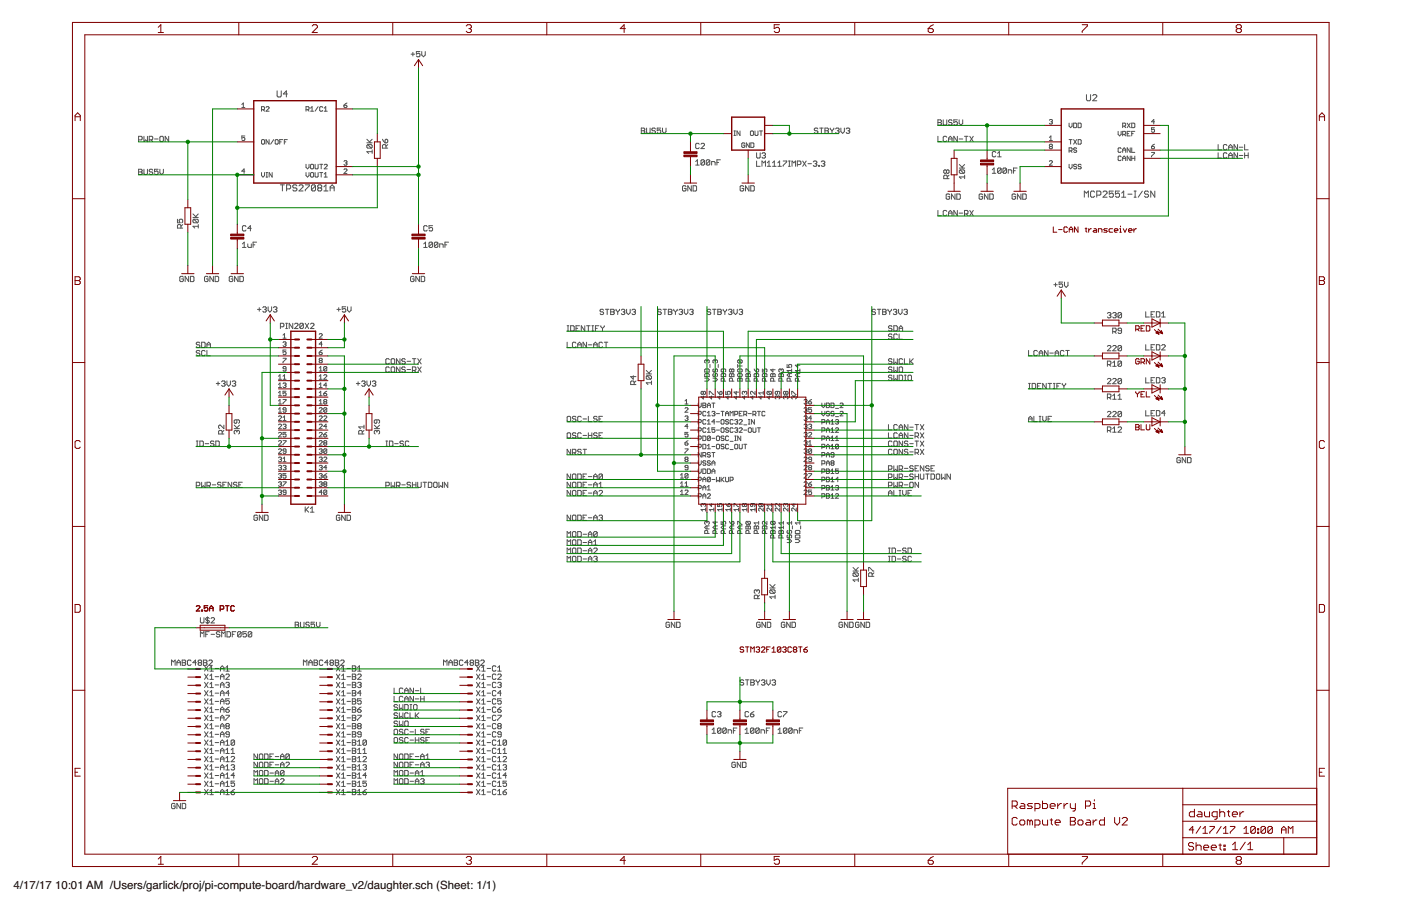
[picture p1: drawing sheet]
<svg xmlns="http://www.w3.org/2000/svg" width="432mm" height="279mm" viewBox="0 0 432 279" stroke-linecap="round" stroke-linejoin="round" font-family="sans-serif">
<defs><g id="words">
<g font-size="3.5">
<text x="4.2" y="274.2">4/17/17</text>
<text x="17" y="274.2">10:01 AM /Users/garlick/proj/pi-compute-board/hardware_v2/daughter.sch (Sheet: 1/1)</text>
</g>
</g></defs>
<g fill="none" stroke="#505050" stroke-width=".31">
<path d="M126.7 16.7h1.1M127.3 16.2v1.1M129.4 15.9h-1.1v.8l.6-.3 .5 .3v.6l-.2 .2h-.6l-.3-.2M130 15.9v1.1l.5 .5 .6-.5v-1.1M74.5 32.2l.5-.4v1.4M74.5 33.2h1M80.6 33.8h.7l.2-.7-.2-.2h-.7v1.4M81.1 33.8l.4 .5M82 33.1l.2-.2 .7 .2-.9 1.2h.9M85.4 28v1.6l.3 .3h.7l.3-.3v-1.6M88.6 29h-1.3l1-1v1.9M94.3 33.8h.7l.2-.7-.2-.2h-.7v1.4"/>
<path d="M94.8 33.8l.4 .5M95.7 34.3h.9M95.7 33.4l.5-.5v1.4M98 32.9l-.9 1.4M99.5 33.1l-.3-.2-.7 .2v1l.3 .2 .7-.2M99.9 33.4l.5-.5v1.4M99.9 34.3h1M106 32.5h.7l.2 .4-.7 .3zM106.9 31.8l-.9 .7M197.7 39.5h.8l.2 .3-.2 .5 .2 .6-.2 .2h-.8zM199.3 39.5v1.4l.3 .2h.5l.3-.2v-1.4M202 39.8l-.3-.3h-.5l-.3 .5 .3 .3h.5l.3 .6-.3 .2h-.5l-.3-.2"/>
<path d="M203.6 39.5h-1v.8l.5-.3 .5 .3v.6l-.2 .2h-.6l-.2-.2M204.2 39.5v1.1l.5 .5 .6-.5v-1.1M252.1 39.8l-.3-.3h-.6l-.2 .5 .2 .3h.6l.3 .6-.3 .2h-.6l-.2-.2M252.6 39.5h1.1M253.2 39.5v1.6M254.3 39.5h.8l.2 .3-.2 .5 .2 .6-.2 .2h-.8zM255.9 39.5l.5 .8M257 39.5l-.6 .8M257.5 39.8l.3-.3h.5l.3 .3-.3 .5M259.2 39.5v1.1l.5 .5 .5-.5v-1.1M260.8 39.8l.3-.3h.5l.3 .3-.3 .5M289.1 37h.8l.3 .2-.3 .6 .3 .5-.3 .3h-.8z"/>
<path d="M289.1 37.8h.8M290.7 37v1.3l.3 .3h.5l.3-.3v-1.3M293.4 37.2l-.2-.2h-.6l-.2 .5 .2 .3h.6l.2 .5-.2 .3h-.6l-.2-.3M295.1 37h-1.1v.8l.5-.3 .6 .3v.5l-.3 .3h-.5l-.3-.3M295.6 37v1.1l.6 .5 .5-.5v-1.1M323.4 37.1l.7-.2 .3 .2-.3 .4M323.9 37.5h.2M324.1 37.5l.3 .3-.3 .4-.7-.2M329.5 38v.9l.5 .5 .4-.5v-.9M330.9 38h.7l.2 .2v.9l-.2 .3h-.7zM332.3 38h.7l.2 .2v.9l-.2 .3h-.7zM334.9 29.2v1.6l.3 .3h.6l.3-.3v-1.6"/>
<path d="M336.8 29.5l.3-.3h.6l.3 .3v.3l-1.2 1.3h1.2M346 38.9h.7l.2-.2-.2-.7h-.7v1.4M346.5 38.9l.4 .5M347.4 38l.9 1.4M348.3 38l-.9 1.4M348.8 38h.7l.3 .2v.9l-.3 .3h-.7zM355.8 37.5h-.9l.7-.6v1.3M355.8 39.4h-.9v.7l.5-.2 .4 .2-.2 .7-.7-.2M42.7 43.1h.8l.3-.2v-.6l-.3-.3h-.8v1.7M42.7 52.2h.8l.3 .3-.3 .5 .3 .6-.3 .2h-.8zM42.7 53h.8M44.4 52.2v1.4l.2 .2h.6l.2-.2v-1.4"/>
<path d="M44.4 42v1.7l.5-.6 .5 .6v-1.7M46 43.1h.8l.3-.2v-.6l-.3-.3h-.8v1.7M46.5 43.1l.6 .6M47.1 52.5l-.3-.3h-.5l-.3 .3 .3 .5h.5l.3 .3-.3 .5h-.5l-.3-.2M47.6 42.9h1.1M48.7 52.2h-1.1v.8l.6-.3 .5 .3v.6l-.2 .2h-.6l-.3-.2M49.3 52.2v1.1l.5 .5 .6-.5v-1.1M49.3 42.3l.3-.3h.5l.3 .3v1.1l-.3 .3h-.5l-.3-.3zM52 42v1.7l-1.1-1.7v1.7M75.5 41.9h-1v.7l.5-.2 .5 .2-.3 .7-.7-.2M75.5 52.8h-1l.7-.7v1.4M80.6 43.3l.2-.2 .7 .2v.9l-.2 .2-.7-.2z"/>
<path d="M80.6 53.2v.9l.5 .5 .4-.5v-.9M82 54.6h.5M82 53.2h.5M82.2 53.2v1.4M82.9 43.1v1.3l-.9-1.3v1.3M83.9 53.2v1.4l-.9-1.4v1.4M84.3 43.1l-.9 1.3M84.8 43.3l.2-.2 .7 .2v.9l-.2 .2-.7-.2zM86.2 43.8h.5M86.4 57h1.3M87 57v1.9M87.1 43.1h-.9v1.3"/>
<path d="M87.6 43.8h.5M88.3 58.3h1l.3-.3v-.7l-.3-.3h-1v1.9M88.6 43.1h-1v1.3M91.5 57.3l-.3-.3h-.6l-.4 .3 .4 .7h.6l.3 .3-.3 .6h-.6l-.4-.3M92.2 57.3l.3-.3h.6l.3 .3v.3l-1.2 1.3h1.2M94.1 57h1.2v.3l-1.2 1.3v.3M94.3 50.7v.9l.5 .5 .4-.5v-.9M94.3 53.2v.9l.5 .5 .4-.5v-.9M95.7 53.4l.2-.2 .7 .2v1l-.2 .2-.7-.2zM95.7 50.9l.2-.2 .7 .2v.9l-.2 .3-.7-.3zM97.1 50.7v1.1l.2 .3 .7-.3v-1.1M97.1 53.2v1.2l.2 .2 .7-.2v-1.2"/>
<path d="M97.2 57.3l-.3-.3h-.6l-.3 .3v1.3M97.2 57.3v1.3l-.3 .3h-.6l-.3-.3M97.2 57.3l-1.2 1.3M98.2 58l-.3-.4 .3-.6h.6l.4 .3-.4 .7M98.2 58h.6M98.2 58l-.3 .3 .3 .6h.6l.4-.3-.4-.6M98.5 53.2h1M98.5 50.7h1M99 50.7v1.4M99 53.2v1.4M99.8 58.9h1.3M99.8 57.6l.7-.6v1.9"/>
<path d="M99.9 50.9l.3-.2 .7 .2-1 1.2h1M99.9 54.6h1M99.9 53.7l.5-.5v1.4M101.7 58h1.3M101.7 58.9v-1.3l.7-.6 .6 .6v1.3M106 49.8l.7-.2 .2 .2-.2 .4M106 52.3l.2-.2 .7 .2-.9 1.2h.9M106.5 50.2h.2M106.7 50.2l.2 .3-.2 .4-.7-.2M113.1 44h1.6M113.1 42.9l1.1 1.1M113.3 44.6h1.1l.3 .3v.5l-.3 .3"/>
<path d="M113.3 44.6l-.2 .3v.5l.2 .3h1.1M113.3 44.6l1.1 1.1M114.7 46.8h-1.6l.5 .5M114.7 46.2v1.1M114.7 42.9l-.8 .9M117.9 42.9l.8 1.1M118.7 43.2l.3-.3 .5 .3v.6l-.3 .2h-.5zM119 45.7v-.8l-.3-.3h-.5l-.3 .3v.8h1.6M119.5 44.6l-.5 .5M197.7 40.3h.8M211.4 57.6l-.2-.3h-.6l-.2 .3v1l.2 .3h.6l.2-.3v-.5h-.5M213.1 57.3v1.6l-1.1-1.6v1.6"/>
<path d="M213.6 57.3h.8l.3 .3v1l-.3 .3h-.8zM214.4 49.8l.5-.5v1.6M214.4 50.9h1.1M215.5 44.5l-.3-.3h-.5l-.3 .3v1.1l.3 .2h.5l.3-.2M216 44.5l.3-.3h.6l.2 .3v.2l-1.1 1.1h1.1M217.1 49.6l-.2-.3h-.6l-.3 .3v1M217.1 49.6v1l-.2 .3h-.6l-.3-.3M217.1 49.6l-1.1 1M218.8 49.6v1l-.3 .3h-.5l-.3-.3M218.8 49.6l-.3-.3h-.5l-.3 .3v1M218.8 49.6l-1.1 1M219.3 50.9v-1.1h.8l.3 .3v.8"/>
<path d="M221 50.1h.5M222 49.3h-1v1.6M226.2 41.8h.5M226.2 40.4h.5M226.4 40.4v1.4M228.1 40.4v1.4l-1-1.4v1.4M229.2 57.6l-.3-.3h-.5l-.3 .3v1l.3 .3h.5l.3-.3v-.5h-.5M229.6 44.3l-.3-.2-.7 .2v.9l.3 .3 .7-.3v-.4h-.5M230.8 57.3v1.6l-1-1.6v1.6M230.9 44.1v1.4l-.9-1.4v1.4M231.4 57.3h.8l.3 .3v1l-.3 .3h-.8zM231.4 44.1h.7l.2 .2v.9l-.2 .3h-.7z"/>
<path d="M231.5 40.4l.7 .2v1l-.2 .2-.7-.2v-1zM232.7 40.4v1.2l.2 .2 .7-.2v-1.2M233.2 47.1v1.4l.3 .2h.5l.3-.2v-1.4M233.2 49.7v1.6h1.1M234.1 40.4h.9M234.5 40.4v1.4M234.8 51.3v-1.6l.6 .5 .5-.5v1.6M234.8 47.4l.3-.3h.5l.3 .3-.3 .5M235.4 47.9h.2M235.6 47.9l.3 .3-.3 .5h-.5l-.3-.2M236.5 51.3h1.1M236.5 50.2l.5-.5v1.6"/>
<path d="M238.1 51.3h1.1M238.1 50.2l.6-.5v1.6M239.8 51.3h1M239.8 50.2l.5-.5v1.6M241.4 49.7h1.1l-1.1 1.6M243 51.3h.6M243 49.7h.6M243.3 49.7v1.6M244.1 51.3v-1.6l.6 .5 .5-.5v1.6M245.7 50.8h.9l.2-.3v-.6l-.2-.2h-.9v1.6M247.4 49.7l1.1 1.6M248.5 49.7l-1.1 1.6"/>
<path d="M249 50.5h1.1M250.7 49.9l.2-.2h.6l.3 .2-.3 .6M251.2 50.5h.3M251.5 50.5l.3 .3-.3 .5h-.6l-.2-.3M252.3 51h.3v.3h-.3zM253.1 49.9l.3-.2h.5l.3 .2-.3 .6M253.7 50.5h.2M253.9 50.5l.3 .3-.3 .5h-.5l-.3-.3M254.3 40.3h.8M256.4 40.3v.8M258.1 40.3h.2M258.3 40.3l.3 .3-.3 .5h-.5l-.3-.2"/>
<path d="M261.3 40.3h.3M261.6 40.3l.3 .3-.3 .5h-.5l-.3-.2M289.1 42v1.7h1.1M291.7 52.6l-.3-.2-.5 .2v.6l.2 .3 .6-.3M291.7 52.6l.3-.2 .5 .2v.6l-.3 .3-.5-.3M291.7 52.6v.6M291.8 42.3l-.3-.3h-.5l-.3 .3v1.1l.3 .3h.5l.3-.3M292 55.1v-.8l-.3-.3h-.6l-.2 .3v.8h1.6M292.4 43.7v-1.1l.5-.6 .5 .6v1.1M292.4 42.9h1M292.5 54l-.5 .6M294.3 59.8v1.6l-1.1-1.6v1.6"/>
<path d="M294.9 59.8h.8l.3 .3v1.1l-.3 .2h-.8zM295.1 42v1.7l-1.1-1.7v1.7M295.6 42.9h1.1M295.7 51.8h1.6M295.7 50.7l1.1 1.1M296 52.4h1l.3 .2v.6l-.3 .3M296 52.4l-.3 .2v.6l.3 .3h1M296 52.4l1 1.1M297.3 42h1M297.3 54.6h-1.6l.5 .5M297.3 54v1.1M297.3 50.7l-.8 .9"/>
<path d="M297.8 42v1.7M298.9 42l1.1 1.7M300 42l-1.1 1.7M304.5 59.8v1.6l-1.1-1.6v1.6M305.1 59.8h.8l.2 .3v1.1l-.2 .2h-.8zM305.8 53.4h1.1M305.8 52.4l.6-.6v1.6M306.9 47l-.3-.3h-.5l-.3 .3v1.1l.3 .3h.5l.3-.3M307.5 47.3l.5-.6v1.7M307.5 48.4h1.1M308.6 52.1v1.1l-.3 .2h-.6l-.2-.2M308.6 52.1l-.3-.3h-.6l-.2 .3v1.1"/>
<path d="M308.6 52.1l-1.1 1.1M310.2 52.1v1.1l-.3 .2h-.5l-.3-.2M310.2 52.1l-.3-.3h-.5l-.3 .3v1.1M310.2 52.1l-1.1 1.1M310.7 53.4v-1h.9l.2 .2v.8M312.4 52.6h.5M313.5 51.8h-1.1v1.6M314.7 59.8v1.6l-1.1-1.6v1.6M315.2 59.8h.8l.3 .3v1.1l-.3 .2h-.8zM323.4 49.8l.3-.2 .7 .2-1 1.1h1M323.4 43.3h1M323.4 42.4l.5-.5v1.4"/>
<path d="M323.7 45.2l-.3 .2 .3 .5 .7-.3-.3-.4M323.7 45.2l-.3-.3 .3-.4 .7 .2-.3 .5M323.7 45.2h.4M329.5 46.5h.7l.2-.2-.2-.7h-.7v1.4M329.5 43.1h.9M329.5 50.7v.9l.5 .5 .4-.5v-.9M330 43.1v1.3M330 46.5l.4 .5M330.9 43.1l.9 1.3M331.8 45.8l-.2-.2-.7 .2 .2 .5 .7 .2-.2 .5-.7-.2M331.8 50.9l-.2-.2-.7 .2 .2 .5 .7 .2-.2 .5-.7-.3M331.8 43.1l-.9 1.3"/>
<path d="M332.3 43.1h.7l.2 .2v.9l-.2 .2h-.7zM333.2 50.9l-.2-.2-.7 .2 .2 .5 .7 .2-.2 .5-.7-.3M337.4 59.2l-.3-.3h-.7l-.3 .3v1.3l.3 .3h.7l.3-.3M340 59.2l.3-.3h.6l.3 .3v.4l-1.2 1.2h1.2M343.1 58.9h-1.2v1l.9-.3 .3 .3v.6l-.3 .3h-.6l-.3-.3M344.6 40.5v.9l.5 .5 .4-.5v-.9M345 58.9h-1.2v1l.9-.3 .3 .3v.6l-.3 .3h-.6l-.3-.3M345.5 45.8l-.2-.2-.7 .2v1l.2 .2 .7-.2M345.5 48.4l-.2-.3-.7 .3v.9l.2 .2 .7-.2M345.7 59.6l.6-.7v1.9M346 47v-.9l.5-.5 .4 .5v.9M346 46.3h.9"/>
<path d="M346 41.4h.7l.2-.2-.2-.7h-.7v1.4M346 49.5v-.9l.5-.5 .4 .5v.9M346 48.8h.9M346.5 41.4l.4 .5M347.4 41.2h.5M347.6 59.9h1.3M348.3 40.5h-.9v1.4h.9M348.3 45.6v1.4l-.9-1.4v1.4M348.3 48.1v1.4l-.9-1.4v1.4M348.8 45.6v1.4h1M348.8 48.1v1.4M348.8 41.2h.5"/>
<path d="M348.8 48.8h1M349.5 58.9h.7M349.8 40.5h-1v1.4M349.8 48.1v1.4M349.9 58.9v1.9M352.1 58.9l-1.3 1.9M354 59.2l-.3-.3h-.6l-.4 .7 .4 .3h.6l.3 .6-.3 .3h-.6l-.4-.3M354.9 47h.9l-.9 1.4M354.9 45.2h.7l.2 .4-.7 .3zM355.8 44.5l-.9 .7M355.9 58.9v1.9l-1.2-1.9v1.9M375.4 47.1v1.6h1.1"/>
<path d="M375.4 44.6v1.6h1.1M378.1 44.9l-.2-.3h-.6l-.2 .3v1l.2 .3h.6l.2-.3M378.1 47.4l-.2-.3h-.6l-.2 .3v1.1l.2 .2h.6l.2-.2M378.7 47.9h1.1M378.7 46.2v-1.1l.5-.5 .6 .5v1.1M378.7 48.7v-1l.5-.6 .6 .6v1M378.7 45.4h1.1M381.4 44.6v1.6l-1.1-1.6v1.6M381.4 47.1v1.6l-1.1-1.6v1.6M382 47.9h1.1M382 45.4h1.1M383.6 47.9h1.1"/>
<path d="M383.6 44.6v1.6h1.1M383.6 47.1v1.6M384.7 47.1v1.6M54.7 67.6v1.1h.8l-.3-.5 .3-.6h.5l.3 .3v.5l-.3 .3M55.8 70.3v-.8l-.3-.2h-.6l-.2 .2v.8h1.6M56.3 69.3l-.5 .5M59.5 67.1h1.6M59.5 66l1.1 1.1M59.8 67.6h1l.3 .3v.5l-.3 .3M59.8 67.6l-.3 .3v.5l.3 .3h1M59.8 67.6l1 1.1M61.1 69.3v1"/>
<path d="M61.1 69.8h-1.6l.5 .5M61.1 66l-.8 .8M74.7 75.2l.6-.5v1.6M74.7 76.3h1.1M75.8 69.9l-.3-.3h-.5l-.3 .3v1.1l.3 .2h.5l.3-.2M76.4 75.2v.8l.2 .3h.8v-1.1M77.4 70.4h-1l.8-.8v1.6M78 75.5h.5M79.1 74.7h-1.1v1.6M130.6 76.3h1.1M130.6 75.2l.5-.5v1.6M131.7 69.9l-.3-.3h-.5l-.3 .3v1.1l.3 .2h.5l.3-.2"/>
<path d="M133.3 75v1l-.2 .3h-.6l-.3-.3M133.3 75l-.2-.3h-.6l-.3 .3v1M133.3 69.6h-1.1v.8l.6-.3 .5 .3v.6l-.2 .2h-.6l-.3-.2M133.3 75l-1.1 1M135 75v1l-.3 .3h-.6l-.2-.3M135 75l-.3-.3h-.6l-.2 .3v1M135 75l-1.1 1M135.5 76.3v-1.1h.8l.3 .3v.8M137.1 75.5h.6M138.2 74.7h-1.1v1.6M289.1 64.9v1.6h1.1M291.8 65.2l-.3-.3h-.5l-.3 .3v1.1l.3 .2h.5l.3-.2"/>
<path d="M292.4 66.5v-1.1l.5-.5 .5 .5v1.1M292.4 65.7h1M292.7 60.1l-.3-.3h-.5l-.3 .3v1.1l.3 .2h.5l.3-.2v-.6h-.5M295.1 64.9v1.6l-1.1-1.6v1.6M295.6 65.7h1.1M297.3 66h.8l.2-.3v-.5l-.2-.3h-.8v1.6M297.8 66l.5 .5M298.9 64.9l1.1 1.6M300 64.9l-1.1 1.6M302.9 60.1l-.3-.3h-.6l-.2 .3v1.1l.2 .2h.6l.3-.2v-.6h-.6M313 60.1l-.3-.3h-.5l-.3 .3v1.1l.3 .2h.5l.3-.2v-.6h-.5M334.2 60.8v-1.9l.6 .7 .6-.7v1.9"/>
<path d="M338 60.2h1l.3-.3v-.7l-.3-.3h-1v1.9M345.7 60.8h1.3M349.5 60.8h.7M56.5 85.5l-.3-.3h-.5l-.3 .3v1.1l.3 .2h.5l.3-.2v-.6h-.5M58.1 85.2v1.6l-1-1.6v1.6M58.7 85.2h.8l.3 .3v1.1l-.3 .2h-.8zM64.1 85.5l-.2-.3h-.6l-.3 .3v1.1l.3 .2h.6l.2-.2v-.6h-.5M65.8 85.2v1.6l-1.1-1.6v1.6M66.3 85.2h.8l.3 .3v1.1l-.3 .2h-.8zM71.8 85.5l-.3-.3h-.6l-.2 .3v1.1l.2 .2h.6l.3-.2v-.6h-.6M73.4 85.2v1.6l-1.1-1.6v1.6M73.9 85.2h.8l.3 .3v1.1l-.3 .2h-.8z"/>
<path d="M79.4 95.4h1M79.9 94.9v1.1M81 94.9l.3-.3h.5l.3 .3-.3 .5M81.5 95.4h.3M81.8 95.4l.3 .3-.3 .5h-.5l-.3-.2M82.6 94.6v1.1l.6 .5 .5-.5v-1.1M84.3 94.9l.2-.3h.6l.2 .3-.2 .5M84.8 95.4h.3M85.1 95.4l.2 .3-.2 .5h-.6l-.2-.2M88.1 99.7h.5M88.3 99.7v1.6M90.2 99.7v1.6l-1.1-1.6v1.6"/>
<path d="M90.8 100l.3-.3h.5l.3 .3v.2l-1.1 1.1h1.1M93.5 100l-.3-.3h-.5l-.3 .3v1M93.5 100v1l-.3 .3h-.5l-.3-.3M93.5 100l-1.1 1M94.1 99.7l1 1.6M95.1 99.7l-1 1.6M95.7 100l.3-.3h.5l.3 .3v.2l-1.1 1.1h1.1M103.8 95.4h1.1M104.4 94.9v1.1M106.6 94.6h-1.1v.8l.5-.2 .6 .2v.6l-.3 .2h-.6l-.2-.2M107.1 94.6v1.1l.6 .5 .5-.5v-1.1M127.6 85.5l-.3-.3h-.5l-.3 .3v1.1l.3 .2h.5l.3-.2v-.6h-.5"/>
<path d="M129.3 85.2v1.6l-1.1-1.6v1.6M129.8 85.2h.8l.3 .3v1.1l-.3 .2h-.8zM186 95.7l-.2-.3h-.6l-.2 .5 .2 .3h.6l.2 .5-.2 .3h-.6l-.2-.3M186.6 95.4h1.1M187.1 95.4v1.6M188.2 95.4h.8l.3 .3-.3 .5 .3 .5-.3 .3h-.8zM188.2 96.2h.8M189.9 95.4l.5 .8M190.4 96.2v.8M190.9 95.4v.3l-.5 .5M191.5 95.7l.3-.3h.5l.3 .3-.3 .5M192 96.2h.3"/>
<path d="M192.3 96.2l.3 .3-.3 .5h-.5l-.3-.3M193.1 95.4v1.1l.6 .5 .5-.5v-1.1M194.8 95.7l.3-.3h.5l.3 .3-.3 .5M195.3 96.2h.3M195.6 96.2l.3 .3-.3 .5h-.5l-.3-.3M203.8 95.7l-.3-.3h-.5l-.3 .5 .3 .3h.5l.3 .5-.3 .3h-.5l-.3-.3M204.4 95.4h1M204.9 95.4v1.6M206 95.4h.8l.3 .3-.3 .5 .3 .5-.3 .3h-.8zM206 96.2h.8M207.6 95.4l.6 .8M208.2 96.2v.8"/>
<path d="M208.7 95.4v.3l-.5 .5M209.3 95.7l.2-.3h.6l.3 .3-.3 .5M209.8 96.2h.3M210.1 96.2l.3 .3-.3 .5h-.6l-.2-.3M210.9 95.4v1.1l.6 .5 .5-.5v-1.1M212.6 95.7l.2-.3h.6l.2 .3-.2 .5M213.1 96.2h.3M213.4 96.2l.2 .3-.2 .5h-.6l-.2-.3M219.1 95.7l-.3-.3h-.6l-.2 .5 .2 .3h.6l.3 .5-.3 .3h-.6l-.2-.3M219.6 95.4h1.1M220.1 95.4v1.6M221.2 95.4h.9l.2 .3-.2 .5 .2 .5-.2 .3h-.9z"/>
<path d="M221.2 96.2h.9M222.9 95.4l.5 .8M223.4 96.2v.8M224 95.4v.3l-.6 .5M224.5 95.7l.3-.3h.5l.3 .3-.3 .5M225 96.2h.3M225.3 96.2l.3 .3-.3 .5h-.5l-.3-.3M226.1 95.4v1.1l.6 .5 .5-.5v-1.1M227.8 95.7l.2-.3h.6l.3 .3-.3 .5M228.3 96.2h.3M228.6 96.2l.3 .3-.3 .5h-.6l-.2-.3M269.8 95.7l-.2-.3h-.6l-.2 .3 .2 .5h.6l.2 .3-.2 .5h-.6l-.2-.3"/>
<path d="M270.4 95.4h1.1M270.9 95.4v1.6M272 95.4h.8l.3 .3-.3 .5 .3 .5-.3 .3h-.8zM272 96.2h.8M273.7 95.4v.3l.5 .5M274.2 96.2v.8M274.7 95.4l-.5 .8M275.3 95.7l.3-.3h.5l.3 .3-.3 .5M275.8 96.2h.3M276.1 96.2l.3 .3-.3 .5h-.5l-.3-.3M276.9 95.4v1.1l.6 .5 .5-.5v-1.1M278.6 95.7l.2-.3h.6l.3 .3-.3 .5"/>
<path d="M279.1 96.2h.3M279.4 96.2l.3 .3-.3 .5h-.6l-.2-.3M324.8 87.8h1.1M325.3 87.3v1M327.5 87h-1.1v.8l.6-.3 .5 .3v.5l-.2 .3h-.6l-.3-.3M328.1 87v1.1l.5 .5 .6-.5v-1.1M341.3 96.7l.3-.3h.5l.3 .3-.3 .5M341.8 97.2h.3M342.1 97.2l.3 .3-.3 .5h-.5l-.3-.3M342.9 96.7l.3-.3h.6l.2 .3-.2 .5M343.5 97.2h.3M343.8 97.2l.2 .3-.2 .5h-.6l-.3-.3"/>
<path d="M345.7 96.7l-.3-.3h-.6l-.2 .3v1M345.7 96.7v1l-.3 .3h-.6l-.2-.3M345.7 96.7l-1.1 1M353.1 96.1v1.7h1.1M354.8 96.9h.5M355.9 96.1h-1.1v1.7h1.1M356.4 96.1h.8l.3 .3v1.1l-.3 .3h-.8zM358 96.7l.6-.6v1.7M358 97.8h1.1M61.6 105.8l-.3-.3h-.5l-.3 .3 .3 .5h.5l.3 .3-.3 .6h-.5l-.3-.3M61.6 108.4l-.3-.3h-.5l-.3 .3 .3 .5h.5l.3 .3-.3 .5h-.5l-.3-.3M62.1 105.5h.8l.3 .3v1.1l-.3 .3h-.8z"/>
<path d="M63.2 108.4l-.3-.3h-.5l-.3 .3v1l.3 .3h.5l.3-.3M63.8 107.2v-1.1l.5-.6 .6 .6v1.1M63.8 108.1v1.6h1.1M63.8 106.3h1.1M66.7 118.3h1M67.2 117.8v1M68.3 117.8l.3-.3h.5l.3 .3-.3 .5M68.8 118.3h.3M69.1 118.3l.3 .3-.3 .5h-.5l-.3-.3M69.9 117.5v1.1l.6 .5 .5-.5v-1.1M71.6 117.8l.2-.3h.6l.2 .3-.2 .5M72.1 118.3h.3"/>
<path d="M72.4 118.3l.2 .3-.2 .5h-.6l-.2-.3M85.8 117h1M85.8 116l.5-.4v1.4M85.8 118.6l.5-.5v1.4M85.8 119.5h1M86.4 100.8h.8l.3-.3v-.5l-.3-.3h-.8v1.6M87.2 103.4l.5-.5v1.4M87.2 117h1M87.2 116l.5-.4v1.4M87.2 104.3h1M87.2 105.6l.7-.2 .3 .2-.3 .5M87.2 110.5h1l-1 1.4"/>
<path d="M87.2 118.3l.7-.2 .3 .2-.3 .5M87.7 106.1h.2M87.7 118.8h.2M87.9 106.1l.3 .3-.3 .4-.7-.2M87.9 118.8l.3 .2-.3 .5-.7-.2M88.1 101.3h.5M88.2 107.9h-1v.7l.5-.2 .5 .2-.3 .8-.7-.3M88.2 113.7h-.7l-.3-.2 .3-.5 .7 .3v.9l-.3 .2-.7-.2M98.4 108.6h.7l.2 .5-.7 .3zM98.4 117h.9M98.4 103.1l.2-.2 .7 .2-.9 1.2h.9M98.4 114.4h.9"/>
<path d="M98.4 113.5l.4-.5v1.4M98.4 116l.4-.4v1.4M98.4 118.6l.4-.5v1.4M98.4 119.5h.9M98.6 111.2l-.2-.2 .2-.5 .7 .2-.2 .5M98.6 111.2l-.2 .2 .2 .5 .7-.2-.2-.5M98.6 111.2h.5M99.3 106.1h-.9l.7-.7v1.4M99.3 107.9l-.9 .7M99.8 115.8l.2-.2 .7 .2-.9 1.2h.9M100.7 118.8h-.9l.7-.7v1.4M100.7 113.3v.9l-.2 .2-.7-.2"/>
<path d="M100.7 113.3l-.7-.3-.2 .3v.9M100.7 113.3l-.9 .9M109.8 118.3h1.1M110.4 117.8v1M111.5 117.8l.2-.3h.6l.2 .3-.2 .5M112 118.3h.3M112.3 118.3l.2 .3-.2 .5h-.6l-.2-.3M113.1 117.5v1.1l.5 .5 .6-.5v-1.1M114.7 117.8l.3-.3h.5l.3 .3-.3 .5M115.3 118.3h.2M115.5 118.3l.3 .3-.3 .5h-.5l-.3-.3M120 110.9l-.3-.3h-.5l-.3 .3v1.1l.3 .2h.5l.3-.2"/>
<path d="M120 113.4l-.3-.2h-.5l-.3 .2v1.1l.3 .3h.5l.3-.3M120.5 110.9l.3-.3h.6l.2 .3v1.1l-.2 .2h-.6l-.3-.2zM120.5 113.4l.3-.2h.6l.2 .2v1.1l-.2 .3h-.6l-.3-.3zM123.3 110.6v1.6l-1.1-1.6v1.6M123.3 113.2v1.6l-1.1-1.6v1.6M124.9 113.4l-.3-.2h-.5l-.3 .5 .3 .3h.5l.3 .5-.3 .3h-.5l-.3-.3M124.9 110.9l-.3-.3h-.5l-.3 .5 .3 .3h.5l.3 .6-.3 .2h-.5l-.3-.2M125.5 114h1.1M125.5 111.4h1.1M127.1 114.2h.8l.3-.2v-.6l-.3-.2h-.8v1.6M127.1 110.6h1.1M127.6 110.6v1.6"/>
<path d="M127.6 114.2l.6 .6M128.7 113.2l1.1 1.6M128.7 110.6l1.1 1.6M129.8 113.2l-1.1 1.6M129.8 110.6l-1.1 1.6M174.8 105.5v1.7h1.1M174.8 100.5h.5M174.8 102.1h.5M175.1 100.5v1.6M175.9 100.5h.8l.3 .2v1.1l-.3 .3h-.8zM177.5 105.8l-.3-.3h-.5l-.3 .3v1.1l.3 .3h.5l.3-.3M177.5 101.3h.6"/>
<path d="M178.1 106.3h1.1M178.1 107.2v-1.1l.5-.6 .6 .6v1.1M178.6 100.5h-1.1v1.6h1.1M180.2 100.5v1.6l-1-1.6v1.6M180.8 105.5v1.7l-1.1-1.7v1.7M180.8 100.5h1.1M181.3 106.3h1.1M181.3 100.5v1.6M182.4 100.5h.6M182.4 102.1h.6M182.7 100.5v1.6M183 106.3h1.1"/>
<path d="M183 107.2v-1.1l.5-.6 .6 .6v1.1M183.5 101.3h.6M184.6 100.5h-1.1v1.6M185.2 100.5l.5 .8M185.7 105.8l-.3-.3h-.5l-.3 .3v1.1l.3 .3h.5l.3-.3M185.7 101.3v.8M186.2 105.5h1.1M186.2 100.5v.2l-.5 .6M186.8 105.5v1.7M195.2 115.9v1l-.8-.8h1.6M195.5 118.6v-.8l-.3-.3h-.6l-.2 .3v.8h1.6M196 117.5l-.5 .5"/>
<path d="M199.2 115.3h1.6M199.2 114.2l1.1 1.1M199.4 115.9h1.1l.3 .2v.6l-.3 .2M199.4 115.9l-.2 .2v.6l.2 .2h1.1M199.4 115.9l1.1 1M200.8 118h-1.6l.5 .6M200.8 117.5v1.1M200.8 114.2l-.8 .8M217.2 116.6h.9l.5 .5-.5 .4h-.9M217.4 113.8h1l.2 .2v.7h-1.4v-.7zM217.4 115.2h1l.2 .2v.7h-1.4v-.7zM217.9 111.2l-.2-.2-.5 .2 .2 .7"/>
<path d="M217.9 111.2v.3M217.9 111.2l.2-.2 .5 .2-.2 .7M218.8 112.4v.9M219.7 116.6h1l.4 .5-.4 .4h-1M220 113.8l-.3 .2 .3 .7 .4-.2 .3-.7 .4 .2-.2 .7M220 115.2l-.3 .2 .3 .7 .4-.2 .3-.7 .4 .2-.2 .7M220.4 111.2l.3-.2 .4 .2-.2 .7M220.4 111.2v.3M220.4 111.2l-.2-.2-.5 .2 .3 .7M221.4 112.4v.9M222.3 115.4l.2-.2 .5 .2 .4-.2 .3 .2v.7h-1.4zM223 113.8v.7l-.3 .2-.4-.2 .2-.7h.9l.3 .2-.3 .7"/>
<path d="M223 115.4v.7M223.2 117.5v-.7l-.7-.2-.2 .2v.7h1.4M224.8 115.4l.2-.2 .5 .2 .5-.2 .2 .2v.7h-1.4zM225.5 114l-.2-.2-.5 .2 .2 .7 .5-.2M225.5 114v.5M225.5 115.4v.7M225.5 114l.2-.2 .5 .2-.2 .7-.5-.2M225.7 117.5v-.7l-.7-.2-.2 .2v.7h1.4M227.4 115.4l.2-.2h.9l.2 .7-.2 .2h-.9zM227.4 116.8l.2-.2 .4 .2 .5-.2 .2 .2v.7h-1.3zM227.4 114l.2-.2h.9l.2 .7-.2 .2h-.9zM227.4 112.4v.9"/>
<path d="M227.4 112.9h1.3M227.6 111l-.2 .2 .2 .7h.9M227.6 111h.9l.2 .2-.2 .7M227.6 111l.9 .9M228 116.8v.7M229.9 114.7v-.9l1.4 .9M229.9 115.4l.2-.2 .5 .2 .5-.2 .2 .2v.7h-1.4zM230.6 115.4v.7M230.8 117.5v-.7l-.7-.2-.2 .2v.7h1.4M232.4 115.4l.3-.2 .4 .2 .5-.2 .2 .2v.7h-1.4zM232.4 113.8l.7 .9M233.1 114l.5-.2 .2 .7-.7 .2z"/>
<path d="M233.1 115.4v.7M233.4 117.5v-.7l-.7-.2-.3 .2v.7h1.4M235 113.8v.9h.7l-.3-.4 .3-.5 .7 .2-.3 .7M235 115.4l.2-.2 .5 .2 .4-.2 .3 .2v.7h-1.4zM235.7 115.4v.7M235.9 117.5v-.7l-.7-.2-.2 .2v.7h1.4M237.5 115.4l.2-.2 .5 .2 .5-.2 .2 .2v.7h-1.4zM238.2 113.8v.9l-.7-.7h1.4M238.2 115.4v.7M238.4 117.5v-.7l-.7-.2-.2 .2v.7h1.4M240.1 115.4l.2-.2 .4 .2 .5-.2 .2 .2v.7h-1.3zM240.7 114v.3"/>
<path d="M240.7 115.4v.7M240.7 114l.3-.2 .4 .2-.2 .7M240.7 114l-.2-.2-.4 .2 .2 .7M241 117.5v-.7l-.7-.2-.2 .2v.7h1.3M242.6 112.4v.9h.7l-.2-.4 .2-.5 .7 .2-.2 .7M243.3 115.2v.9M243.5 117.5v-.7l-.7-.2-.2 .2v.7h1.4M244 115.2h-.9l-.5 .5 .5 .4h.9M244 113.8v.9M244 114.3h-1.4l.5 .4M245.8 112.4v.9l-.7-.7h1.4M245.8 115.2v.9"/>
<path d="M246.1 117.5v-.7l-.7-.2-.3 .2v.7h1.4M246.5 115.2h-.9l-.5 .5 .5 .4h.9M246.5 113.8v.9M246.5 114.3h-1.4l.5 .4M274.9 103.3l-.2-.3h-.6l-.3 .3 .3 .5h.6l.2 .3-.2 .5h-.6l-.3-.2M274.9 110.9l-.2-.3h-.6l-.3 .3 .3 .5h.6l.2 .3-.2 .5h-.6l-.3-.2M274.9 100.7l-.2-.2h-.6l-.3 .2 .3 .6h.6l.2 .2-.2 .6h-.6l-.3-.3M274.9 113.4l-.2-.2h-.6l-.3 .2 .3 .6h.6l.2 .2-.2 .6h-.6l-.3-.3M274.9 116l-.2-.3h-.6l-.3 .3 .3 .5h.6l.2 .3-.2 .5h-.6l-.3-.2M275.5 115.7v1.6l.5-.5 .6 .5v-1.6M275.5 100.5h.8l.3 .2v1.1l-.3 .3h-.8zM275.5 110.6v1.6l.5-.5 .6 .5v-1.6"/>
<path d="M275.5 113.2v1.6l.5-.6 .6 .6v-1.6M276.6 103.3l-.3-.3h-.6l-.2 .3v1.1l.2 .2h.6l.3-.2M277.1 115.7h.8l.3 .3v1.1l-.3 .2h-.8zM277.1 102.1v-1.1l.5-.5 .6 .5v1.1M277.1 103v1.6h1.1M277.1 101.3h1.1M277.4 113.2h.5l.3 .2v1.1l-.3 .3h-.5l-.3-.3v-1.1zM278.2 110.9l-.3-.3h-.5l-.3 .3v1.1l.3 .2h.5l.3-.2M278.7 110.6v1.6h1.1M278.7 115.7h.6M278.7 117.3h.6M279 115.7v1.6"/>
<path d="M279.8 116l.3-.3h.5l.3 .3v1.1l-.3 .2h-.5l-.3-.2zM280.4 110.6v1.6M280.6 111.4l.9 .8M281.5 110.6l-1.1 1.1M317 118.2h.6M317 108.1v1.6h1.1M317 119.9h.6M317.3 118.2v1.7M318.1 118.2h.8l.3 .3v1.1l-.3 .3h-.8zM319.7 108.4l-.2-.3h-.6l-.3 .3v1l.3 .3h.6l.2-.3M319.7 119h.6M320.3 108.9h1.1"/>
<path d="M320.3 109.7v-1.1l.5-.5 .6 .5v1.1M320.8 118.2h-1.1v1.7h1.1M322.5 118.2v1.7l-1.1-1.7v1.7M323 108.1v1.6l-1.1-1.6v1.6M323 118.2h1.1M323.6 108.9h1.1M323.6 118.2v1.7M324.7 118.2h.5M324.7 119.9h.5M324.9 118.2v1.7M325.2 108.9h1.1M325.2 109.7v-1.1l.5-.5 .6 .5v1.1"/>
<path d="M325.7 119h.6M326.8 118.2h-1.1v1.7M327.4 118.2l.5 .8M327.9 108.4l-.3-.3h-.5l-.3 .3v1l.3 .3h.5l.3-.3M327.9 119v.9M328.5 108.1h1.1M328.5 118.2v.3l-.6 .5M329 108.1v1.6M341.3 106.8l.3-.2h.5l.3 .2v.3l-1.1 1.1h1.1M341.3 112.4h.8l.3-.2v-.6l-.3-.2h-.8v1.6M341.3 117l.3-.3h.5l.3 .3v.2l-1.1 1.1h1.1M341.8 112.4l.6 .6"/>
<path d="M342.9 102.3h.9l.2-.3v-.5l-.2-.3h-.9v1.6M342.9 106.8l.3-.2h.6l.2 .2v.3l-1.1 1.1h1.1M342.9 117l.3-.3h.6l.2 .3v.2l-1.1 1.1h1.1M342.9 111.9l.6-.5v1.6M342.9 113h1.1M343.5 102.3l.5 .5M345.7 102h-.9l-.2-.3 .2-.5h.6l.3 .3v1.1l-.3 .2h-.6l-.2-.2M345.7 106.8l-.3-.2h-.6l-.2 .2v1.1M345.7 111.6l-.3-.2h-.6l-.2 .2v1.1M345.7 117l-.3-.3h-.6l-.2 .3v1.1M345.7 106.8v1.1l-.3 .3h-.6l-.2-.3M345.7 111.6v1.1l-.3 .3h-.6l-.2-.3"/>
<path d="M345.7 117v1.1l-.3 .2h-.6l-.2-.2M345.7 106.8l-1.1 1.1M345.7 117l-1.1 1.1M345.7 111.6l-1.1 1.1M353.1 106.3v1.6h1.1M353.1 116.5v1.6h1.1M354.8 107.1h.5M354.8 117.3h.5M355.9 106.3h-1.1v1.6h1.1M355.9 116.5h-1.1v1.6h1.1M356.4 116.5h.8l.3 .2v1.1l-.3 .3h-.8zM356.4 106.3h.8l.3 .3v1.1l-.3 .2h-.8z"/>
<path d="M358 106.6l.3-.3h.6l.2 .3v.2l-1.1 1.1h1.1M358 116.7l.3-.2h.6l.2 .2-.2 .6M358.6 117.3h.3M358.9 117.3l.2 .2-.2 .6h-.6l-.3-.3M60.5 137.6h.5M60.5 136h.5M60.8 136v1.6M61.6 136h.8l.3 .3v1.1l-.3 .2h-.8zM63.2 136.8h1.1M66 136.3l-.3-.3h-.6l-.2 .3 .2 .5h.6l.3 .3-.3 .5h-.6l-.2-.2M66.5 136h.8l.3 .3v1.1l-.3 .2h-.8zM68.5 133.8v-.8l-.3-.3h-.6l-.2 .3v.8h1.6"/>
<path d="M69 131.1v1.1l-1.1-1.1-.5 .3v.5l.2 .3M69 132.7l-.5 .6M72.2 131.1l1.1 1.1M72.2 132.2h1.6M73 133l-.3-.3-.5 .3v.6l.3 .2M73 129.5v.8l-.3 .3-.5-.3v-.6l.3-.2h1l.3 .2v.6l-.3 .3M73 133l.3-.3 .5 .3v.6l-.3 .2M73 133v.3M73.8 131.1l-.8 .8M85.8 126.2l.5-.5v1.4M85.8 131l.3-.2 .7 .2-1 1.2h1M85.8 121.1l.5-.5v1.4"/>
<path d="M85.8 123.7l.5-.5v1.4M85.8 122h1M85.8 128.5l.3-.2 .7 .2-1 1.2h1M85.8 124.6h1M85.8 127.1h1M85.8 133.6l.3-.3 .7 .3-1 1.1h1M85.8 136.1l.3-.2 .7 .2-1 1.2h1M85.8 138.7l.3-.3 .7 .3-1 1.1h1M87.2 128.7l.5-.4v1.4M87.2 123.2h1l-1 1.4M87.2 131l.7-.2 .3 .2-.3 .5M87.2 135.9h1l-1 1.4"/>
<path d="M87.2 129.7h1M87.7 131.5h.2M87.9 131.5l.3 .2-.3 .5-.7-.2M88.2 139.1h-.7l-.3-.2 .3-.5 .7 .3v.9l-.3 .2-.7-.2M88.2 133.3h-1v.7l.5-.2 .5 .2-.3 .7-.7-.2M88.2 120.6h-1v.7l.5-.2 .5 .2-.3 .7-.7-.2M88.2 126.4h-.7l-.3-.2 .3-.5 .7 .3v.9l-.3 .2-.7-.2M98.4 131l.2-.2 .7 .2-.9 1.2h.9M98.4 126l.2-.3 .7 .3-.9 1.1h.9M98.4 128.5l.2-.2 .7 .2-.9 1.2h.9M98.4 133.6l.2-.3 .7 .3-.9 1.1h.9M98.4 136.1l.2-.2 .7 .2-.9 1.2h.9"/>
<path d="M98.4 138.7l.7-.3 .2 .3-.2 .4M98.4 121.1l.4-.5v1.4M98.4 123.7l.4-.5v1.4M98.4 122h.9M98.4 124.6h.9M98.8 139.1h.3M99.1 139.1l.2 .3-.2 .4-.7-.2M99.8 121.3h.7l.2 .5-.7 .2zM99.8 134h.7l.2 .5-.7 .2zM99.8 128.5l.2-.2 .7 .2-.9 1.2h.9M100 123.9l-.2 .2 .2 .5 .7-.2-.2-.5M100 123.9l-.2-.2 .2-.5 .7 .2-.2 .5"/>
<path d="M100 136.6l-.2-.2 .2-.5 .7 .2-.2 .5M100 136.6l-.2 .2 .2 .5 .7-.2-.2-.5M100 123.9h.5M100 136.6h.5M100.7 131.5h-.9l.7-.7v1.4M100.7 133.3l-.9 .7M100.7 126l-.7-.3-.2 .3v.9M100.7 138.7l-.2-.3-.7 .3v.9M100.7 126v.9l-.2 .2-.7-.2M100.7 138.7v.9l-.2 .2-.7-.2M100.7 120.6l-.9 .7M100.7 126l-.9 .9"/>
<path d="M100.7 138.7l-.9 .9M111.6 133.8v-.8l-.2-.3h-.6l-.2 .3v.8h1.6M112.2 132.7l-.6 .6M112.2 131.7h-1.6l.5 .5M112.2 131.1v1.1M115.4 131.1l1 1.1M115.4 132.2h1.6M116.2 129.5v.8l-.3 .3-.5-.3v-.6l.2-.2h1.1l.3 .2v.6l-.3 .3M116.2 133l-.3-.3-.5 .3v.6l.2 .2M116.2 133l.2-.3 .6 .3v.6l-.3 .2M116.2 133v.3M117 131.1l-.8 .8"/>
<path d="M118.9 137.6h.6M118.9 136h.6M119.2 136v1.6M120 136h.8l.3 .3v1.1l-.3 .2h-.8zM121.6 136.8h1.1M124.4 136.3l-.3-.3h-.6l-.2 .3 .2 .5h.6l.3 .3-.3 .5h-.6l-.2-.2M126 136.3l-.3-.3h-.5l-.3 .3v1.1l.3 .2h.5l.3-.2M174.8 128.7l.3-.3h.5l.3 .3v1.1l-.3 .2h-.5l-.3-.2zM174.8 133.7l.3-.2h.5l.3 .2v1.1l-.3 .3h-.5l-.3-.3zM175.9 138.6v1.6l-1.1-1.6v1.6M176.4 139.6h.8l.3-.2v-.6l-.3-.2h-.8v1.6M177 139.6l.5 .6"/>
<path d="M177.5 128.7l-.3-.3h-.5l-.3 .3 .3 .5h.5l.3 .3-.3 .5h-.5l-.3-.2M177.5 133.7l-.3-.2h-.5l-.3 .2 .3 .6h.5l.3 .3-.3 .5h-.5l-.3-.3M179.2 138.8l-.3-.2h-.6l-.2 .2 .2 .6h.6l.3 .2-.3 .6h-.6l-.2-.3M179.2 128.7l-.3-.3h-.6l-.2 .3v1.1l.2 .2h.6l.3-.2M179.2 133.7l-.3-.2h-.6l-.2 .2v1.1l.2 .3h.6l.3-.3M179.7 138.6h1.1M179.7 134.3h1.1M179.7 129.2h1.1M180.2 138.6v1.6M181.3 128.4v1.6h1.1M181.3 133.5v1.6M181.3 134.3h1.1"/>
<path d="M182.4 133.5v1.6M184.1 128.7l-.3-.3h-.6l-.2 .3 .2 .5h.6l.3 .3-.3 .5h-.6l-.2-.2M184.1 133.7l-.3-.2h-.6l-.2 .2 .2 .6h.6l.3 .3-.3 .5h-.6l-.2-.3M184.6 134.3h.5M184.6 129.2h.5M185.7 128.4h-1.1v1.6h1.1M185.7 133.5h-1.1v1.6h1.1M211.1 124.6h.9M211.1 126l.2-.3 .7 .3-.9 1.1h.9M211.1 128.5l.7-.2 .2 .2-.2 .5M211.1 136.6h.7l.2 .5-.7 .2zM211.1 138.4h.9l-.9 1.4"/>
<path d="M211.1 123.7l.5-.5v1.4M211.6 129h.2M211.8 129l.2 .2-.2 .5-.7-.3M212 131.5h-.9l.7-.7v1.4M212 133.3h-.9v.7l.5-.2 .4 .2-.2 .7-.7-.2M212 135.9l-.9 .7M215.2 124.3v.9l.5 .5 .4-.5v-.9M215.2 127.8h.7l.2-.2-.2-.7h-.7v1.3M215.2 130.3h.7l.2-.7-.2-.2h-.7v1.4M215.2 132.9h.7l.2-.7-.2-.3h-.7v1.4M215.2 135.4h.7l.2-.7-.2-.2h-.7v1.4M215.2 137.9h.7l.2-.7-.2-.2h-.7v1.4"/>
<path d="M216.1 139.6v1.3l-.9-1.3v1.3M216.6 124.3h.7l.3 .2-.3 .5 .3 .5-.3 .2h-.7zM216.6 134.5h.7l.3 .2v.9l-.3 .3h-.7zM216.6 137h.7l.3 .2v1l-.3 .2h-.7zM216.6 125h.7M216.8 120.9l-.3-.2-.4 .2 .2 .7 .5-.2M216.8 120.9l.2-.2 .5 .2-.3 .7-.4-.2M216.8 122.1v.9l-.7-.7h1.4M216.8 120.9v.5M217.6 132.2l-.3-.3-.7 .3v.9l.3 .2 .7-.2M217.6 127.1l-.3-.2-.7 .2v.9l.3 .2 .7-.2M217.6 129.6l-.3-.2-.7 .2v1l.3 .2 .7-.2"/>
<path d="M218 129.9l.5-.5v1.4M218 125h.9M218 125.7v-.9l.5-.5 .4 .5v.9M218 128.2h.9M218 127.3l.5-.4v1.3M218 132.4l.5-.5v1.4M218 137.5l.5-.5v1.4M218 130.8h.9M218 133.3h.9M218 138.4h.9M218.6 121.6v-.9l1.4 .9M218.9 134.7l-.7-.2-.2 .2v.9"/>
<path d="M218.9 139.8l-.7-.2-.2 .4 .7 .3 .2 .4-.2 .2-.7-.2M218.9 134.7v.9l-.2 .3-.7-.3M218.9 134.7l-.9 .9M219.3 122.1v.9l-.7-.7h1.4M219.4 124.3h.9M219.4 127.1l.7-.2 .2 .2-.2 .5M219.4 135.2h.9M219.4 137.7h.9M219.4 139.6h.9M219.9 124.3v1.4M219.9 139.6v1.3M219.9 127.6h.2"/>
<path d="M220.1 127.6l.2 .2-.2 .4-.7-.2M220.3 131.9h-.9v.7l.5-.2 .4 .2-.2 .7-.7-.2M220.3 130.1h-.9l.7-.7v1.4M220.8 127.6h1M220.8 130.1h1M220.8 132.6h1M221 134.5l.8 .2v.9l-.3 .3-.7-.3v-.9zM221 137l.8 .2v1l-.3 .2-.7-.2v-1zM221.1 120.7l.7 .9M221.8 120.9l.5-.2 .2 .7-.7 .2zM221.8 122.1v.9l-.7-.7h1.4M222.2 126.9h1"/>
<path d="M222.5 129.4l.7 .2v1l-.3 .2-.7-.2v-1zM222.5 131.9l.7 .3v.9l-.3 .2-.7-.2v-.9zM222.7 126.9v1.3M223.2 134.7l-.3-.2-.7 .2 .3 .5 .7 .2-.3 .5-.7-.3M223.2 137.2l-.3-.2-.7 .2 .3 .5 .7 .2-.3 .5-.7-.2M223.6 128.2v-.9l.5-.4 .5 .4v.9M223.6 127.6h1M223.7 120.7v.9h.7l-.2-.4 .2-.5 .7 .2-.2 .7M224.4 122.1v.9l-.7-.7h1.4M224.6 129.6l-.3-.2-.7 .2 .3 .5 .7 .2-.3 .5-.7-.2M224.6 132.2l-.3-.3-.7 .3 .3 .4 .7 .3-.3 .4-.7-.2M224.6 134.7l-.3-.2-.7 .2v.9l.3 .3 .7-.3"/>
<path d="M224.6 137.2l-.3-.2-.7 .2v1l.3 .2 .7-.2M225 128.2v-1.3l.5 .4 .5-.4v1.3M225 136.1h1M225 138.6h1M226 132.2l-.3-.3-.7 .3v.9l.3 .2 .7-.2M226 129.6l-.3-.2-.7 .2v1l.3 .2 .7-.2M226.4 129.6l.7-.2 .3 .2-.3 .5M226.4 127.8h.7l.3-.7-.3-.2h-.7v1.3M226.4 137.2l.3-.2 .7 .2v1l-.3 .2-.7-.2zM226.4 132.2l.7-.3 .3 .3-.3 .4M226.4 134.5h.5M226.4 135.9h.5"/>
<path d="M226.7 134.5v1.4M226.9 130.1h.2M226.9 132.6h.2M226.9 122.1v.9l-.7-.7h1.4M226.9 120.7v.9l-.7-.7h1.4M227.1 130.1l.3 .2-.3 .5-.7-.2M227.1 132.6l.3 .3-.3 .4-.7-.2M227.8 137v1.2l.3 .2 .7-.2v-1.2M227.8 127.6h.5M227.8 129.6l.3-.2 .7 .2-1 1.2h1M227.8 132.2l.3-.3 .7 .3-1 1.1h1M228.3 134.5v1.4l-.9-1.4v1.4"/>
<path d="M228.8 126.9h-1v1.3h1M229.2 127.8h.7l.3-.7-.3-.2h-.7v1.3M229.2 131h1M229.2 132.6h1M229.2 137h1M229.5 120.9l.2-.2 .5 .2-.3 .7M229.5 120.9l-.3-.2-.4 .2 .2 .7M229.5 120.9v.3M229.5 122.1v.9l-.7-.7h1.4M229.7 127.8l.5 .4M229.7 137v1.4M230.6 127.6h1"/>
<path d="M230.6 129.4h.5M230.6 130.8h.5M230.6 132.2l.3-.3 .7 .3v.9l-.2 .2-.8-.2zM230.9 129.4v1.4M232 122.1v.9l-.7-.7h1.4M232.1 127.8h.6l.3-.2-.3-.7h-.6v1.3M232.1 131.9v1.2l.2 .2 .7-.2v-1.2M232.5 127.8l.5 .4M232.5 129.4v1.4l-.9-1.4v1.4M232.7 120.7v.9l-.9-.9-.5 .2 .2 .7M233.4 126.9h1M233.4 131.9h1"/>
<path d="M233.9 126.9v1.3M233.9 131.9v1.4M234.5 122.1v.9l-.7-.7h1.4M235.2 121.2h-1.4l.5 .4M235.2 120.7v.9M235.8 127.1l-.3-.2-.7 .2v.9l.3 .2 .7-.2M236.6 120.7h1l.2 .2-.2 .7M236.6 120.7l-.2 .2 .2 .7h1M236.6 120.7l1 .9M237.1 122.1v.9l-.7-.7h1.4M239.6 120.7v.7l-.2 .2-.5-.2 .3-.7h.9l.2 .2-.2 .7M239.6 122.3l.3-.2 .4 .2-.2 .7"/>
<path d="M239.6 122.3l-.2-.2-.5 .2 .3 .7M239.6 122.3v.3M242.2 120.9l-.3-.2-.4 .2 .2 .7 .5-.2M242.2 122.3l-.3-.2-.4 .2 .2 .7M242.2 120.9l.2-.2 .5 .2-.3 .7-.4-.2M242.2 122.3l.2-.2 .5 .2-.3 .7M242.2 120.9v.5M242.2 122.3v.3M244 121.6v-.9l1.4 .9M244.7 122.3v.3M244.7 122.3l.2-.2 .5 .2-.2 .7M244.7 122.3l-.2-.2-.5 .2 .2 .7"/>
<path d="M247.8 128.5l.7-.2 .2 .2-.2 .5M247.8 123.4l.7-.2 .2 .2-.2 .5M247.8 126l.7-.3 .2 .3-.2 .4M247.8 131l.7-.2 .2 .2-.2 .5M247.8 133.6l.7-.3 .2 .3-.2 .4M247.8 136.1l.7-.2 .2 .2-.2 .5M247.8 138.7l.7-.3 .2 .3-.2 .4M248.3 126.4h.2M248.3 123.9h.2M248.3 131.5h.2M248.3 134h.2M248.3 139.1h.2"/>
<path d="M248.3 136.6h.2M248.3 129h.2M248.5 134l.2 .3-.2 .4-.7-.2M248.5 131.5l.2 .2-.2 .5-.7-.2M248.5 123.9l.2 .2-.2 .5-.7-.2M248.5 126.4l.2 .3-.2 .4-.7-.2M248.5 129l.2 .2-.2 .5-.7-.3M248.5 136.6l.2 .2-.2 .5-.7-.2M248.5 139.1l.2 .3-.2 .4-.7-.2M249.2 123.9h.7l.2 .5-.7 .2zM249.2 131l.7-.2 .2 .2-.2 .5M249.2 133.6l.2-.3 .7 .3-.9 1.1h.9"/>
<path d="M249.2 137.3h.9M249.2 136.4l.5-.5v1.4M249.7 131.5h.2M249.9 131.5l.2 .2-.2 .5-.7-.2M250.1 125.7h-.9v.7l.5-.2 .4 .2-.2 .7-.7-.2M250.1 138.7v.9l-.2 .2-.7-.2M250.1 138.7l-.2-.3-.7 .3v.9M250.1 129h-.9l.7-.7v1.4M250.1 138.7l-.9 .9M250.1 123.2l-.9 .7M253.3 124.3v.9l.5 .5 .4-.5v-.9M253.3 126.9v.9l.5 .4 .4-.4v-.9"/>
<path d="M253.3 130.3h.7l.2-.7-.2-.2h-.7v1.4M253.3 132.9h.7l.2-.7-.2-.3h-.7v1.4M253.3 135.4h.7l.2-.7-.2-.2h-.7v1.4M253.3 137.9h.7l.2-.7-.2-.2h-.7v1.4M254.7 130.8v-.9l.5-.5 .4 .5v.9M254.7 124.3h.7l.2 .2v1l-.2 .2h-.7zM254.7 130.1h.9M254.7 135.2h.9M254.7 132.6h.9M254.7 137.7h.9M254.7 133.3v-.9l.5-.5 .4 .5v.9M254.7 135.9v-1l.5-.4 .4 .4v1"/>
<path d="M254.7 138.4v-.9l.5-.5 .4 .5v.9M255.6 127.1l-.7-.2-.2 .4 .7 .3 .2 .4-.2 .2-.7-.2M256.1 124.3h.7l.2 .2v1l-.2 .2h-.7zM256.1 130.8h.9M256.1 135.9h.9M256.1 133.3h.9M256.1 138.4h.9M256.1 132.4l.5-.5v1.4M256.1 129.9l.5-.5v1.4M256.1 134.9l.5-.4v1.4M256.1 137.5l.5-.5v1.4M257 127.1l-.2-.2-.7 .2 .2 .5 .7 .2-.2 .4-.7-.2"/>
<path d="M257.5 134.9l.5-.4v1.4M257.5 129.6l.7-.2 .2 .2-.2 .5M257.5 135.9h.9M257.5 132.2l.2-.3 .7 .3-.9 1.1h.9M257.5 128.5h.9M257.5 125.9h.9M258 130.1h.2M258.2 130.1l.2 .2-.2 .5-.7-.2M258.4 137.2l-.2-.2-.7 .2v1M258.4 137.2v1l-.2 .2-.7-.2M258.4 137.2l-.9 1M258.9 124.5l.2-.2 .7 .2-.9 1.2h.9"/>
<path d="M258.9 127.1l.2-.2 .7 .2-.9 1.1h.9M273.8 130.9v1.7h1.1M273.8 133.5v1.6h1.1M274.9 136.3l-.2-.3h-.6l-.3 .3v1.1l.3 .2h.6l.2-.2M274.9 138.8l-.2-.2h-.6l-.3 .2v1.1l.3 .3h.6l.2-.3M275.5 136.3l.2-.3h.6l.3 .3v1.1l-.3 .2h-.6l-.2-.2zM275.5 138.8l.2-.2h.6l.3 .2v1.1l-.3 .3h-.6l-.2-.3zM276.6 131.2l-.3-.3h-.6l-.2 .3v1.1l.2 .3h.6l.3-.3M276.6 133.7l-.3-.2h-.6l-.2 .2v1.1l.2 .3h.6l.3-.3M277.1 135.1v-1.1l.5-.5 .6 .5v1.1M277.1 132.6v-1.1l.5-.6 .6 .6v1.1M277.1 134.3h1.1"/>
<path d="M277.1 131.7h1.1M278.2 136v1.6l-1.1-1.6v1.6M278.2 138.6v1.6l-1.1-1.6v1.6M279.8 136.3l-.2-.3h-.6l-.3 .3 .3 .5h.6l.2 .3-.2 .5h-.6l-.3-.2M279.8 130.9v1.7l-1.1-1.7v1.7M279.8 133.5v1.6l-1.1-1.6v1.6M279.8 138.8l-.2-.2h-.6l-.3 .2 .3 .6h.6l.2 .2-.2 .6h-.6l-.3-.3M280.4 136.8h1.1M280.4 139.4h1.1M280.4 134.3h1.1M280.4 131.7h1.1M282 136h1.1"/>
<path d="M282 134.6h.8l.3-.3v-.6l-.3-.2h-.8v1.6M282 139.6h.8l.3-.2v-.6l-.3-.2h-.8v1.6M282 130.9h1.1M282.6 139.6l.5 .6M282.6 130.9v1.7M282.6 136v1.6M282.6 134.6l.5 .5M283.7 138.6l1 1.6M283.7 136l1 1.6M283.7 133.5l1 1.6M283.7 130.9l1 1.7M284.7 138.6l-1 1.6"/>
<path d="M284.7 136l-1 1.6M284.7 133.5l-1 1.6M284.7 130.9l-1 1.7M317 129.2h1.1M317 130v-1.1l.6-.5 .5 .5v1.1M318.6 128.4v1.6h1.1M320.3 130h.5M320.3 128.4h.5M320.5 128.4v1.6M321.4 128.4v1.1l.5 .5 .6-.5v-1.1M323 129.2h.6M324.1 128.4h-1.1v1.6h1.1"/>
<path d="M341.3 127.1l.3-.2h.5l.3 .2v.3l-1.1 1.1h1.1M341.3 132.8h.8l.3-.3v-.6l-.3-.2h-.8v1.6M341.3 122.6h.8l.3-.3v-.5l-.3-.3h-.8v1.6M341.8 122.6l.6 .5M341.8 132.8l.6 .5M342.9 127.1l.3-.2h.6l.2 .2v.3l-1.1 1.1h1.1M342.9 133.3h1.1M342.9 122l.6-.5v1.6M342.9 132.2l.6-.5v1.6M342.9 123.1h1.1M344.6 131.9l.2-.2h.6l.3 .2v.3l-1.1 1.1h1.1M344.6 123.1h1.1"/>
<path d="M344.6 122l.5-.5v1.6M345.7 127.1l-.3-.2h-.6l-.2 .2v1.1M345.7 127.1v1.1l-.3 .3h-.6l-.2-.3M345.7 127.1l-1.1 1.1M353.1 126.6v1.6h1.1M354.8 127.4h.5M355.9 126.6h-1.1v1.6h1.1M356.4 126.6h.8l.3 .3v1.1l-.3 .2h-.8zM359.1 127.4h-1.1l.9-.8v1.6M60.5 149.8h.8l.3-.3v-.5l-.3-.3h-.8v1.6M62.1 148.7v1.6l.6-.5 .5 .5v-1.6M63.8 149.8h.8l.3-.3v-.5l-.3-.3h-.8v1.6"/>
<path d="M64.3 149.8l.6 .5M65.4 149.5h1.1M68.1 149l-.2-.3h-.6l-.2 .3 .2 .5h.6l.2 .3-.2 .5h-.6l-.2-.2M68.7 149.5h.5M69.8 148.7h-1.1v1.6h1.1M71.4 148.7v1.6l-1.1-1.6v1.6M73 149l-.2-.3h-.6l-.2 .3 .2 .5h.6l.2 .3-.2 .5h-.6l-.2-.2M73.6 149.5h.5M74.7 148.7h-1.1v1.6h1.1M79.4 159.1l-.3-.2h-.6l-.2 .2v1.1l.2 .3h.6l.3-.3v-.5h-.6M81 158.9v1.6l-1.1-1.6v1.6M81.6 158.9h.8l.2 .2v1.1l-.2 .3h-.8z"/>
<path d="M85.8 148.8l.7-.2 .3 .2-.3 .5M85.8 141.2l.7-.2 .3 .2-.3 .5M85.8 143.7l.7-.2 .3 .2-.3 .5M85.8 146.3l.7-.3 .3 .3-.3 .4M85.8 151.4l.7-.3 .3 .3-.3 .4M86.3 141.7h.2M86.3 144.2h.2M86.3 146.7h.2M86.3 149.3h.2M86.3 151.8h.2M86.5 146.7l.3 .3-.3 .4-.7-.2M86.5 144.2l.3 .2-.3 .5-.7-.2"/>
<path d="M86.5 141.7l.3 .2-.3 .5-.7-.3M86.5 149.3l.3 .2-.3 .5-.7-.2M86.5 151.8l.3 .3-.3 .4-.7-.2M87.2 141.4l.5-.4v1.4M87.2 143.7l.7-.2 .3 .2-.3 .5M87.2 148.6h1l-1 1.4M87.2 142.4h1M87.7 144.2h.2M87.9 144.2l.3 .2-.3 .5-.7-.2M88.2 146h-1v.7l.5-.2 .5 .2-.3 .7-.7-.2M88.2 151.8h-.7l-.3-.2 .3-.5 .7 .3v.9l-.3 .2-.7-.2M94.1 156.3v1.6"/>
<path d="M94.3 157.1l.8 .8M95.1 156.3l-1 1.1M95.7 156.9l.5-.6v1.6M95.7 157.9h1.1M98.4 141.2l.7-.2 .2 .2-.2 .5M98.4 148.8l.7-.2 .2 .2-.2 .5M98.4 143.7l.7-.2 .2 .2-.2 .5M98.4 146.3l.7-.3 .2 .3-.2 .4M98.8 141.7h.3M98.8 144.2h.3M98.8 146.7h.3M98.8 149.3h.3"/>
<path d="M99.1 141.7l.2 .2-.2 .5-.7-.3M99.1 144.2l.2 .2-.2 .5-.7-.2M99.1 146.7l.2 .3-.2 .4-.7-.2M99.1 149.3l.2 .2-.2 .5-.7-.2M99.3 151.8h-.9l.7-.7v1.4M99.8 146.7h.7l.2 .5-.7 .2zM99.8 141.2l.2-.2 .7 .2-.9 1.2h.9M100 149.3l-.2-.2 .2-.5 .7 .2-.2 .5M100 149.3l-.2 .2 .2 .5 .7-.2-.2-.5M100 149.3h.5M100.7 144.2h-.9l.7-.7v1.4M100.7 151.4l-.2-.3-.7 .3v.9"/>
<path d="M100.7 151.4v.9l-.2 .2-.7-.2M100.7 146l-.9 .7M100.7 151.4l-.9 .9M104.8 159.1l-.3-.2h-.6l-.2 .2v1.1l.2 .3h.6l.3-.3v-.5h-.6M106.4 158.9v1.6l-1.1-1.6v1.6M107 158.9h.8l.2 .2v1.1l-.2 .3h-.8zM118.9 149.8h.8l.3-.3v-.5l-.3-.3h-.8v1.6M120.5 148.7v1.6l.6-.5 .5 .5v-1.6M122.2 149.8h.8l.3-.3v-.5l-.3-.3h-.8v1.6M122.7 149.8l.6 .5M123.8 149.5h1.1M126.6 149l-.3-.3h-.6l-.2 .3 .2 .5h.6l.3 .3-.3 .5h-.6l-.2-.2"/>
<path d="M127.1 149.5h1.1M127.1 148.7v1.6M128.2 148.7v1.6M128.7 148.7v1.4l.3 .2h.6l.2-.2v-1.4M130.4 148.7h1.1M130.9 148.7v1.6M132 148.7h.8l.3 .3v1.1l-.3 .2h-.8zM133.6 149l.3-.3h.6l.2 .3v1.1l-.2 .2h-.6l-.3-.2zM135.3 148.7v1.6l.5-.5 .6 .5v-1.6M138 148.7v1.6l-1.1-1.6v1.6M175.9 146.2v1.6l-1.1-1.6v1.6M175.9 148.7v1.6l-1.1-1.6v1.6"/>
<path d="M175.9 151.2v1.7l-1.1-1.7v1.7M175.9 158.9v1.6l-1.1-1.6v1.6M176.4 151.5l.3-.3h.5l.3 .3v1.1l-.3 .3h-.5l-.3-.3zM176.4 149l.3-.3h.5l.3 .3v1.1l-.3 .2h-.5l-.3-.2zM176.4 146.4l.3-.2h.5l.3 .2v1.1l-.3 .3h-.5l-.3-.3zM176.7 158.9h.5l.3 .2v1.1l-.3 .3h-.5l-.3-.3v-1.1zM178.1 158.9h.8l.3 .2v1.1l-.3 .3h-.8zM178.1 148.7h.8l.3 .3v1.1l-.3 .2h-.8zM178.1 146.2h.8l.3 .2v1.1l-.3 .3h-.8zM178.1 151.2h.8l.3 .3v1.1l-.3 .3h-.8zM179.7 159.7h.5M179.7 149.5h.5"/>
<path d="M179.7 147h.5M179.7 152.1h.5M180.8 158.9h-1.1v1.6h1.1M180.8 148.7h-1.1v1.6h1.1M180.8 146.2h-1.1v1.6h1.1M180.8 151.2h-1.1v1.7h1.1M181.3 159.7h1.1M181.3 149.5h1.1M181.3 147h1.1M181.3 152.1h1.1M183 159.7h1.1M183 152.9v-1.1l.5-.6 .6 .6v1.1"/>
<path d="M183 149.5h1.1M183 147h1.1M183 147.8v-1.1l.5-.5 .6 .5v1.1M183 150.3v-1.1l.5-.5 .6 .5v1.1M183 152.1h1.1M184.6 159.1l.3-.2h.5l.3 .2-.3 .6M184.6 151.5l.3-.3h.5l.3 .3v.3l-1.1 1.1h1.1M184.6 150.3h1.1M184.6 149.2l.5-.5v1.6M185.1 159.7h.3M185.4 159.7l.3 .3-.3 .5h-.5l-.3-.3M185.7 146.4l-.3-.2h-.5l-.3 .2v1.1"/>
<path d="M185.7 146.4v1.1l-.3 .3h-.5l-.3-.3M185.7 146.4l-1.1 1.1M209.7 147.4h1M209.7 150h1M209.7 152.5h1M209.7 149.1l.5-.5v1.4M209.7 151.6l.5-.5v1.4M209.7 146.5l.5-.5v1.4M211.1 150h.9M211.1 151.4l.2-.3 .7 .3-.9 1.1h.9M211.1 149.1l.5-.5v1.4M211.3 141.7l-.2 .2 .2 .5 .7-.3-.2-.4"/>
<path d="M211.3 141.7l-.2-.3 .2-.4 .7 .2-.2 .5M211.3 141.7h.5M212 144.2h-.7l-.2-.2 .2-.5 .7 .2v1l-.2 .2-.7-.2M212 146.3l-.2-.3-.7 .3v.9M212 146.3v.9l-.2 .2-.7-.2M212 146.3l-.9 .9M215.2 148.1h.7l.2-.7-.2-.2h-.7v1.4M215.2 142.1v.9l.5 .5 .4-.5v-.9M215.2 144.6v1l.5 .4 .4-.4v-1M215.2 150.6h.7l.2-.7-.2-.2h-.7v1.4M215.2 153.2h.7l.2-.7-.2-.2h-.7v1.3M216.6 151.1v-.9l.5-.5 .5 .5v.9"/>
<path d="M216.6 144.6h.7l.3 .3v.9l-.3 .2h-.7zM216.6 153.6v-.9l.5-.4 .5 .4v.9M216.6 140.5h.7l.3-.7-.3-.2h-.7v1.3M216.6 148.6v-1l.5-.4 .5 .4v1M216.6 147.9h1M216.6 150.4h1M216.6 153h1M216.8 155.5l-.3-.2-.4 .2 .2 .7M216.8 155.5l.2-.2 .5 .2-.3 .7M216.8 155.5v.2M217.1 140.5l.5 .4M217.5 157.1h-1.4l.4 .5"/>
<path d="M217.5 156.7v.9M217.6 142.3l-.3-.2-.7 .2 .3 .5 .7 .2-.3 .5-.7-.2M218 144.6h.7l.2 .3v.9l-.2 .2h-.7zM218 151.1h.9M218 152.5l.2-.2 .7 .2-.9 1.1h.9M218 150.2l.5-.5v1.4M218.9 147.4v.9l-.2 .3-.7-.3M218.9 147.4l-.7-.2-.2 .2v.9M218.9 142.3l-.7-.2-.2 .5 .7 .2 .2 .5-.2 .2-.7-.2M218.9 147.4l-.9 .9M219.3 155.3v.9l-.7-.7h1.4M219.4 143.5v-.9l.5-.5 .4 .5v.9"/>
<path d="M219.4 146v-.9l.5-.5 .4 .5v.9M219.4 142.8h.9M219.4 147.9h.9M219.4 145.3h.9M220 157.1h-1.4l.5 .5M220 156.7v.9M220.8 147.2v1.4l.5-.5 .5 .5v-1.4M221.1 155.3v.9h.7l-.2-.5 .2-.4 .7 .2-.2 .7M222.2 147.2v1.4M222.5 147.9l.7 .7M222.5 157.1h-1.4l.5 .5M222.5 156.7v.9"/>
<path d="M223.2 147.2l-1 .9M223.6 147.2v1.1l.3 .3 .7-.3v-1.1M223.7 155.3l.7 .9M224.4 155.5l.5-.2 .2 .7-.7 .2zM225 148.1h.7l.3-.7-.3-.2h-.7v1.4M225.1 157.1h-1.4l.5 .5M225.1 156.7v.9M226.2 156.2v-.9l1.4 .9M227.6 157.1h-1.4l.5 .5M227.6 156.7v.9M229.5 155.5l.2-.2 .5 .2-.3 .7-.4-.2M229.5 155.5l-.3-.2-.4 .2 .2 .7 .5-.2"/>
<path d="M229.5 155.5v.5M230.2 156.7v.9M230.2 157.1h-1.4l.4 .5M232 155.3v.7l-.2 .2-.5-.2 .2-.7h1l.2 .2-.2 .7M232.7 157.1h-1.4l.5 .5M232.7 156.7v.9M234.1 155.3h.9l.2 .2-.2 .7M234.1 155.3l-.3 .2 .3 .7h.9M234.1 155.3l.9 .9M235.2 156.7v.9l-.9-.9-.5 .2 .3 .7M237.8 156.7v.9l-.9-.9-.5 .2 .2 .7M237.8 155.3v.9"/>
<path d="M237.8 155.7h-1.4l.5 .5M240.3 155.3v.9l-.9-.9-.5 .2 .3 .7M240.3 156.7v.9l-.9-.9-.5 .2 .3 .7M242.2 155.5l-.3-.2-.4 .2 .2 .7M242.2 155.5l.2-.2 .5 .2-.3 .7M242.2 155.5v.2M242.9 156.7v.9l-1-.9-.4 .2 .2 .7M244.7 155.3v.9l-.7-.7h1.4M245.4 156.7v.9l-.9-.9-.5 .2 .2 .7M247.8 141.2l.2-.2 .7 .2-.9 1.2h.9M247.8 143.7l.2-.2 .7 .2-.9 1.2h.9M247.8 146.3l.2-.3 .7 .3-.9 1.1h.9"/>
<path d="M247.8 148.8l.2-.2 .7 .2-.9 1.2h.9M247.8 151.4l.2-.3 .7 .3-.9 1.1h.9M249.2 146h.9l-.9 1.4M249.2 149.3h.7l.2 .5-.7 .2zM249.4 144.2l-.2-.2 .2-.5 .7 .2-.2 .5M249.4 144.2h.5M249.4 144.2l-.2 .2 .2 .5 .7-.2-.2-.5M250.1 141.7h-.7l-.2-.3 .2-.4 .7 .2v.9l-.2 .3-.7-.3M250.1 151.1h-.9v.7l.5-.2 .4 .2-.2 .7-.7-.2M250.1 148.6l-.9 .7M253.3 140.5h.7l.2-.7-.2-.2h-.7v1.3M253.3 143h.7l.2-.7-.2-.2h-.7v1.4"/>
<path d="M253.3 145.6h.7l.2-.7-.2-.3h-.7v1.4M253.3 148.1h.7l.2-.7-.2-.2h-.7v1.4M253.3 150.6h.7l.2-.7-.2-.2h-.7v1.4M253.3 153.2h.7l.2-.7-.2-.2h-.7v1.3M254.7 143.5v-.9l.5-.5 .4 .5v.9M254.7 144.6h.7l.2 .3-.2 .4 .2 .5-.2 .2h-.7zM254.7 147.2h.7l.2 .2-.2 .5 .2 .4-.2 .3h-.7zM254.7 149.7h.7l.2 .2-.2 .5 .2 .5-.2 .2h-.7zM254.7 152.3h.7l.2 .2-.2 .5 .2 .4-.2 .2h-.7zM254.7 140.3h.9M254.7 142.8h.9M254.7 147.9h.7"/>
<path d="M254.7 145.3h.7M254.7 150.4h.7M254.7 153h.7M254.7 140.9v-.9l.5-.4 .4 .4v.9M256.1 147.6l.5-.4v1.4M256.1 146h.9M256.1 148.6h.9M256.1 151.1h.9M256.1 153.6h.9M256.1 152.7l.5-.4v1.3M256.1 145.1l.5-.5v1.4M256.1 150.2l.5-.5v1.4"/>
<path d="M256.3 142.8l-.2-.2 .2-.5 .7 .2-.2 .5M256.3 142.8h.5M256.3 142.8l-.2 .2 .2 .5 .7-.2-.2-.5M257 140.3h-.7l-.2-.3 .2-.4 .7 .2v.9l-.2 .2-.7-.2M257.5 152.5l.2-.2 .7 .2-.9 1.1h.9M257.5 149.9l.7-.2 .2 .2-.2 .5M258 150.4h.2M258.2 150.4l.2 .2-.2 .5-.7-.2M258.4 144.6h-.9v.7l.5-.2 .4 .2-.2 .7-.7-.2M258.4 147.9h-.9l.7-.7v1.4M273.8 144.7h.9l.2-.3v-.5l-.2-.3h-.9v1.6M273.8 147.3h.9l.2-.3v-.6l-.2-.2h-.9v1.6"/>
<path d="M273.8 149.8h.9l.2-.3v-.5l-.2-.3h-.9v1.6M273.8 152.9v-1.1l.6-.6 .5 .6v1.1M273.8 152.1h1.1M275.5 143.6v1.6l.5-.5 .6 .5v-1.6M275.5 146.2v1.6l.5-.5 .6 .5v-1.6M275.5 148.7v1.6l.5-.5 .6 .5v-1.6M275.5 151.2v1.7h1.1M277.1 144.7h.8l.3-.3v-.5l-.3-.3h-.8v1.6M277.1 147.3h.8l.3-.3v-.6l-.3-.2h-.8v1.6M277.1 149.8h.8l.3-.3v-.5l-.3-.3h-.8v1.6M277.1 151.2h.5M277.1 152.9h.5"/>
<path d="M277.4 151.2v1.7M277.6 144.7l.6 .5M277.6 147.3l.6 .5M277.6 149.8l.6 .5M278.2 151.2v1.1l.5 .6 .6-.6v-1.1M278.7 149.5h1.1M278.7 144.4h1.1M278.7 147h1.1M279.8 152.1h.6M280.4 149l.2-.3h.6l.3 .3v1.1l-.3 .2h-.6l-.2-.2zM280.9 151.2h-1.1v1.7h1.1M281.5 143.9l-.3-.3h-.6l-.2 .3 .2 .5h.6l.3 .3-.3 .5h-.6l-.2-.2"/>
<path d="M281.5 146.4l-.3-.2h-.6l-.2 .2 .2 .6h.6l.3 .3-.3 .5h-.6l-.2-.3M282 144.4h.6M282 146.2v1.6M282 147h1.1M283.1 143.6h-1.1v1.6h1.1M283.1 148.7v1.6l-1.1-1.6v1.6M283.1 146.2v1.6M283.7 146.2v1.3l.2 .3h.6l.2-.3v-1.3M284.7 143.6v1.6l-1-1.6v1.6M285.3 146.2h1.1M285.8 146.2v1.6M286.4 143.9l-.3-.3h-.5l-.3 .3 .3 .5h.5l.3 .3-.3 .5h-.5l-.3-.2"/>
<path d="M286.9 144.4h.6M286.9 146.2h.8l.3 .2v1.1l-.3 .3h-.8zM288 143.6h-1.1v1.6h1.1M288.6 146.4l.2-.2h.6l.2 .2v1.1l-.2 .3h-.6l-.2-.3zM290.2 146.2v1.6l.5-.5 .6 .5v-1.6M292.9 146.2v1.6l-1.1-1.6v1.6M363.8 141.4l-.3-.3h-.5l-.3 .3v1.1l.3 .2h.5l.3-.2v-.6h-.5M365.4 141.1v1.6l-1-1.6v1.6M366 141.1h.8l.3 .3v1.1l-.3 .2h-.8zM174.8 168.1v-1.6l.5 .5 .6-.5v1.6M174.8 170.6v-1.6l.5 .6 .6-.6v1.6M174.8 165.6v-1.7l.5 .6 .6-.6v1.7"/>
<path d="M174.8 173.2v-1.6l.5 .5 .6-.5v1.6M176.4 166.8l.3-.3h.5l.3 .3v1l-.3 .3h-.5l-.3-.3zM176.4 164.2l.3-.3h.5l.3 .3v1.1l-.3 .3h-.5l-.3-.3zM176.4 169.3l.3-.3h.5l.3 .3v1.1l-.3 .2h-.5l-.3-.2zM176.4 171.8l.3-.2h.5l.3 .2v1.1l-.3 .3h-.5l-.3-.3zM178.1 169h.8l.3 .3v1.1l-.3 .2h-.8zM178.1 171.6h.8l.3 .2v1.1l-.3 .3h-.8zM178.1 163.9h.8l.3 .3v1.1l-.3 .3h-.8zM178.1 166.5h.8l.3 .3v1l-.3 .3h-.8zM179.7 172.4h1.1M179.7 169.8h1.1M179.7 164.8h1.1"/>
<path d="M179.7 167.3h1.1M181.3 170.6v-1l.6-.6 .5 .6v1M181.3 168.1v-1.1l.6-.5 .5 .5v1.1M181.3 173.2v-1.1l.6-.5 .5 .5v1.1M181.3 172.4h1.1M181.3 169.8h1.1M181.3 165.6v-1.1l.6-.6 .5 .6v1.1M181.3 164.8h1.1M181.3 167.3h1.1M183 160.5v-1.1l.5-.5 .6 .5v1.1M183 169.3l.2-.3h.6l.3 .3v.3l-1.1 1h1.1M183 171.8l.2-.2h.6l.3 .2-.3 .6"/>
<path d="M183 168.1h1.1M183 167l.5-.5v1.6M183.5 172.4h.3M183.8 172.4l.3 .3-.3 .5h-.6l-.2-.3M184.1 164.2l-.3-.3h-.6l-.2 .3v1.1M184.1 164.2v1.1l-.3 .3h-.6l-.2-.3M184.1 164.2l-1.1 1.1M217.9 161l-.2-.2-.5 .2 .2 .7M217.9 161v.2M217.9 162.2v.9M217.9 161l.2-.2 .5 .2-.2 .7M218.1 164.5v-.7l-.7-.2-.2 .2v.7h1.4"/>
<path d="M218.6 162.2h-.9l-.5 .4 .5 .5h.9M220.4 160.8v.9l-.7-.7h1.4M220.4 162.2v.9M220.7 164.5v-.7l-.7-.2-.3 .2v.7h1.4M221.1 162.2h-.9l-.5 .4 .5 .5h.9M222.3 160.8v.9h.7l-.3-.5 .3-.4 .7 .2-.3 .7M223 162.2v.9M223.2 164.5v-.7l-.7-.2-.2 .2v.7h1.4M223.7 162.2h-1l-.4 .4 .4 .5h1M224.8 160.8l.7 .9M225.5 161l.5-.2 .2 .7-.7 .2zM225.5 162.2v.9"/>
<path d="M225.7 164.5v-.7l-.7-.2-.2 .2v.7h1.4M226.2 162.2h-.9l-.5 .4 .5 .5h.9M227.4 161.7v-.9l1.3 .9M228 162.2v.9M228.3 164.5v-.7l-.7-.2-.2 .2v.7h1.3M228.7 162.2h-.9l-.4 .4 .4 .5h.9M230.1 160.8l-.2 .2 .2 .7h1M230.1 162.2l.5 .2 .5-.2 .2 .2v.7h-1.4v-.7zM230.1 160.8h1l.2 .2-.2 .7M230.1 160.8l1 .9M230.6 162.4v.7M230.8 164.5v-.7l-.7-.2-.2 .2v.7h1.4"/>
<path d="M232.7 162.2l.4 .2 .5-.2 .2 .2v.7h-1.4v-.7zM233.1 162.4v.7M233.4 164.5v-.7l-.7-.2-.3 .2v.7h1.4M233.8 161.2h-1.4l.5 .5M233.8 160.8v.9M235.2 162.2l.5 .2 .4-.2 .3 .2v.7h-1.4v-.7zM235.7 162.4v.7M235.9 164.5v-.7l-.7-.2-.2 .2v.7h1.4M236.4 160.8v.9l-1-.9-.4 .2 .2 .7M237.5 163.8l.2-.2 .5 .2 .5-.2 .2 .2v.7h-1.4zM237.7 160.8h1l.2 .2-.2 .7M237.7 160.8l-.2 .2 .2 .7h1"/>
<path d="M237.7 160.8l1 .9M238.2 163.8v.7M238.4 165.9v-.7l-.7-.2-.2 .2v.7h1.4M238.9 162.2v.9M238.9 162.6h-1.4l.5 .5M240.1 163.8l.2-.2 .4 .2 .5-.2 .2 .2v.7h-1.3zM240.7 163.8v.7M241 165.9v-.7l-.7-.2-.2 .2v.7h1.3M241.4 160.8v.9M241.4 162.2v.9M241.4 162.6h-1.3l.4 .5M241.4 161.2h-1.3l.4 .5"/>
<path d="M242.6 166.4h.9l.5 .5-.5 .4h-.9M242.8 163.6l-.2 .7 .5 .2 .2-.7 .5-.2 .2 .2-.2 .7M242.8 165l-.2 .2 .2 .7 .5-.2 .2-.7 .5 .2-.2 .7M244 161.2h-1.4l.5 .5M244 160.8v.9M244.2 162.2v.9M245.1 163.8l.3-.2h.9l.2 .2v.7h-1.4zM245.1 165.2l.3-.2h.9l.2 .2v.7h-1.4zM245.1 166.4h1l.4 .5-.4 .4h-1M246.5 161.2h-1.4l.5 .5M246.5 160.8v.9M246.8 162.2v.9"/>
<path d="M262.9 176.1h1.6M262.9 175l1.1 1.1M263.2 176.7h1.1l.2 .2v.6l-.2 .2M263.2 176.7l-.3 .2v.6l.3 .2h1.1M263.2 176.7l1.1 1M264.5 178.8h-1.6l.6 .6M264.5 178.3v1.1M264.5 175l-.8 .8M267.7 176.1v-1.1l1.6 1.1M268.8 177.7v-.8l-.3-.2h-.5l-.3 .2v.8h1.6M269.3 176.7l-.5 .5M273.8 173.2h.6"/>
<path d="M273.8 171.6h.6M273.8 170.6h.6M273.8 169h.6M274.1 169v1.6M274.1 171.6v1.6M274.9 171.6h.8l.3 .2v1.1l-.3 .3h-.8zM274.9 169h.8l.3 .3v1.1l-.3 .2h-.8zM276.6 172.4h1M276.6 169.8h1M279.3 169.3l-.3-.3h-.5l-.3 .3 .3 .5h.5l.3 .3-.3 .5h-.5l-.3-.2M279.3 171.8l-.3-.2h-.5l-.3 .2 .3 .6h.5l.3 .3-.3 .5h-.5l-.3-.3M279.8 169h.8l.3 .3v1.1l-.3 .2h-.8z"/>
<path d="M280.9 171.8l-.3-.2h-.5l-.3 .2v1.1l.3 .3h.5l.3-.3M61.8 190.5v1.3l.2 .3h.6l.3-.3v-1.3M61.8 196.4v-1.6l.5 .5 .6-.5v1.6M63.4 195.6h.5M63.9 190.2v2.2M64.5 190.8l-.3-.3h-.5l-.3 .3 .3 .5h.5l.3 .3-.3 .5h-.5l-.3-.3M64.5 194.8h-1.1v1.6M65 195.6h1.1M65 190.8l.3-.3h.5l.3 .3v.2l-1.1 1.1h1.1M67.8 195.1l-.3-.3h-.5l-.3 .3 .3 .5h.5l.3 .3-.3 .5h-.5l-.3-.2M68.3 196.4v-1.6l.6 .5 .5-.5v1.6M70 194.8h.8l.2 .3v1.1l-.2 .2h-.8z"/>
<path d="M71.6 195.6h.5M72.7 194.8h-1.1v1.6M74.3 195.1l-.3-.3h-.5l-.3 .3v1.1M74.3 195.1v1.1l-.3 .2h-.5l-.3-.2M74.3 195.1l-1.1 1.1M75.9 194.8h-1v.8l.8-.3 .2 .3v.6l-.2 .2h-.6l-.2-.2M77.6 195.1l-.3-.3h-.5l-.3 .3v1.1M77.6 195.1v1.1l-.3 .2h-.5l-.3-.2M77.6 195.1l-1.1 1.1M91 191.9h.8l.3 .3-.3 .5 .3 .5-.3 .3h-.8zM91 192.7h.8M92.6 191.9v1.3l.3 .3h.5l.3-.3v-1.3"/>
<path d="M95.3 192.2l-.2-.3h-.6l-.2 .5 .2 .3h.6l.2 .5-.2 .3h-.6l-.2-.3M97 191.9h-1.1v.8l.8-.3 .3 .3v.5l-.3 .3h-.5l-.3-.3M97.5 191.9v1.1l.6 .5 .5-.5v-1.1M206.4 192.2l-.3-.3h-.6l-.2 .3v1l.2 .3h.6l.3-.3v-.5h-.6M208 191.9v1.6l-1.1-1.6v1.6M208.5 191.9h.9l.2 .3v1l-.2 .3h-.9zM233.3 182.2l-.3-.3-.5 .3v.5l.2 .3M233.3 182.2l.3-.3 .5 .3v.5l-.3 .3M233.3 182.2v.2M233.6 184.6v-.8l-.3-.3h-.6l-.2 .3v.8h1.6M234.1 183.5l-.5 .6M234.3 192.2l-.3-.3h-.5l-.3 .3v1l.3 .3h.5l.3-.3v-.5h-.6"/>
<path d="M235.9 191.9v1.6l-1.1-1.6v1.6M236.5 191.9h.8l.3 .3v1l-.3 .3h-.8zM237.3 181.3h1.6M237.3 180.3l1.1 1M237.5 181.9h1.1l.3 .3v.5l-.3 .3M237.5 181.9l-.2 .3v.5l.2 .3h1.1M237.5 181.9l1.1 1.1M238.9 184.1h-1.6l.5 .5M238.9 183.5v1.1M238.9 180.3l-.8 .8M241.9 192.2l-.3-.3h-.5l-.3 .3v1l.3 .3h.5l.3-.3v-.5h-.5M243.5 191.9v1.6l-1-1.6v1.6"/>
<path d="M244.1 191.9h.8l.3 .3v1l-.3 .3h-.8zM259.7 192.2l-.3-.3h-.5l-.3 .3v1l.3 .3h.5l.3-.3v-.5h-.6M261.3 191.9v1.6l-1.1-1.6v1.6M261.9 191.9h.8l.3 .3v1l-.3 .3h-.8zM264.8 192.2l-.3-.3h-.6l-.2 .3v1l.2 .3h.6l.3-.3v-.5h-.6M266.4 191.9v1.6l-1.1-1.6v1.6M267 191.9h.8l.2 .3v1l-.2 .3h-.8zM52.9 205.2v-1.6l.5 .5 .6-.5v1.6M54.5 205.2v-1.1l.6-.5 .5 .5v1.1M54.5 204.4h1.1M56.2 204.4h.8M56.2 203.6h.8l.2 .2-.2 .6 .2 .5-.2 .3h-.8z"/>
<path d="M58.9 203.8l-.3-.2h-.5l-.3 .2v1.1l.3 .3h.5l.3-.3M60.5 204.4h-1.1l.8-.8v1.6M61.3 204.4h.6M61.3 204.4l-.2-.3 .2-.5h.6l.2 .2-.2 .6M61.3 204.4l-.2 .2 .2 .6h.6l.2-.3-.2-.5M62.7 204.4h.8M62.7 203.6h.8l.3 .2-.3 .6 .3 .5-.3 .3h-.8zM63 205.3l1.1 1.7M63 207.9l1.1 1.6M63 210.4l1.1 1.6M63 213l1.1 1.6M63 215.5l1.1 1.6"/>
<path d="M63 218l1.1 1.7M64.1 205.3l-1.1 1.7M64.1 207.9l-1.1 1.6M64.1 210.4l-1.1 1.6M64.1 213l-1.1 1.6M64.1 215.5l-1.1 1.6M64.1 218l-1.1 1.7M64.3 203.8l.3-.2h.6l.2 .2v.3l-1.1 1.1h1.1M64.7 205.9l.5-.6v1.7M64.7 208.4l.5-.5v1.6M64.7 211l.5-.6v1.6M64.7 213.5l.5-.5v1.6"/>
<path d="M64.7 216l.5-.5v1.6M64.7 218.6l.5-.6v1.7M64.7 207h1.1M64.7 209.5h1.1M64.7 212h1.1M64.7 214.6h1.1M64.7 217.1h1.1M64.7 219.7h1.1M66.3 206.1h1.1M66.3 208.7h1.1M66.3 211.2h1.1M66.3 213.8h1.1"/>
<path d="M66.3 216.3h1.1M66.3 218.8h1.1M67.9 206.1h1.1M67.9 207v-1.1l.6-.6 .5 .6v1.1M67.9 209.5v-1.1l.6-.5 .5 .5v1.1M67.9 212v-1l.6-.6 .5 .6v1M67.9 214.6v-1.1l.6-.5 .5 .5v1.1M67.9 217.1v-1.1l.6-.5 .5 .5v1.1M67.9 219.7v-1.1l.6-.6 .5 .6v1.1M67.9 208.7h1.1M67.9 211.2h1.1M67.9 213.8h1.1"/>
<path d="M67.9 216.3h1.1M67.9 218.8h1.1M69.6 218.8h.8l.3 .6-.3 .3h-.5l-.3-.3zM69.6 210.7l.3-.3h.5l.3 .3-.3 .5M69.6 208.2l.3-.3h.5l.3 .3v.2l-1.1 1.1h1.1M69.6 207h1.1M69.6 205.9l.5-.6v1.7M70.1 211.2h.3M70.4 211.2l.3 .3-.3 .5h-.5l-.3-.2M70.7 215.5h-1.1v.8l.8-.3 .3 .3v.6l-.3 .2h-.5l-.3-.2M70.7 213.8h-1.1l.8-.8v1.6M70.7 218l-1.1 .8"/>
<path d="M93.5 205.2v-1.6l.6 .5 .5-.5v1.6M95.2 204.4h1M95.2 205.2v-1.1l.5-.5 .5 .5v1.1M96.8 203.6h.8l.3 .2-.3 .6 .3 .5-.3 .3h-.8zM96.8 204.4h.8M99.5 203.8l-.2-.2h-.6l-.3 .2v1.1l.3 .3h.6l.2-.3M101.2 204.4h-1.1l.8-.8v1.6M102 204.4h.5M102 204.4l-.3-.3 .3-.5h.5l.3 .2-.3 .6M102 204.4l-.3 .2 .3 .6h.5l.3-.3-.3-.5M103.3 203.6h.9l.2 .2-.2 .6 .2 .5-.2 .3h-.9zM103.3 204.4h.9"/>
<path d="M103.7 205.3l1.1 1.7M103.7 207.9l1.1 1.6M103.7 210.4l1.1 1.6M103.7 213l1.1 1.6M103.7 215.5l1.1 1.6M103.7 218l1.1 1.7M104.8 205.3l-1.1 1.7M104.8 207.9l-1.1 1.6M104.8 210.4l-1.1 1.6M104.8 213l-1.1 1.6M104.8 215.5l-1.1 1.6M104.8 218l-1.1 1.7"/>
<path d="M105 203.8l.2-.2h.6l.3 .2v.3l-1.1 1.1h1.1M105.3 207h1.1M105.3 209.5h1.1M105.3 212h1.1M105.3 214.6h1.1M105.3 217.1h1.1M105.3 219.7h1.1M105.3 205.9l.6-.6v1.7M105.3 208.4l.6-.5v1.6M105.3 211l.6-.6v1.6M105.3 213.5l.6-.5v1.6M105.3 216l.6-.5v1.6"/>
<path d="M105.3 218.6l.6-.6v1.7M107 206.1h1M107 208.7h1M107 211.2h1M107 213.8h1M107 216.3h1M107 218.8h1M108.6 205.3h.8l.3 .3-.3 .5 .3 .6-.3 .3h-.8zM108.6 206.1h.8M108.6 207.9h.8l.3 .3-.3 .5 .3 .5-.3 .3h-.8zM108.6 208.7h.8M108.6 210.4h.8l.3 .3-.3 .5 .3 .6-.3 .2h-.8z"/>
<path d="M108.6 211.2h.8M108.6 213h.8l.3 .2-.3 .6 .3 .5-.3 .3h-.8zM108.6 213.8h.8M108.6 215.5h.8l.3 .3-.3 .5 .3 .6-.3 .2h-.8zM108.6 216.3h.8M108.6 218h.8l.3 .3-.3 .5 .3 .6-.3 .3h-.8zM108.6 218.8h.8M110.2 218.8h.8l.3 .6-.3 .3h-.5l-.3-.3zM110.2 207h1.1M110.2 208.2l.3-.3h.5l.3 .3v.2l-1.1 1.1h1.1M110.2 210.7l.3-.3h.5l.3 .3-.3 .5M110.2 205.9l.6-.6v1.7"/>
<path d="M110.8 211.2h.2M111 211.2l.3 .3-.3 .5h-.5l-.3-.2M111.3 213.8h-1.1l.8-.8v1.6M111.3 215.5h-1.1v.8l.6-.3 .5 .3v.6l-.3 .2h-.5l-.3-.2M111.3 218l-1.1 .8M121.5 212.2v1.6h1M121.5 214.7v1.7h1M122.5 217.6l-.2-.3h-.6l-.2 .5 .2 .3h.6l.2 .5-.2 .3h-.6l-.2-.3M123.1 219.8v1.6l.5-.5 .6 .5v-1.6M123.1 217.3v1.6l.5-.5 .6 .5v-1.6M124.2 215l-.3-.3h-.5l-.3 .3v1.1l.3 .3h.5l.3-.3M124.2 212.5l-.3-.3h-.5l-.3 .3v1.1l.3 .2h.5l.3-.2"/>
<path d="M124.7 215.5h1.1M124.7 213h1.1M124.7 213.8v-1.1l.6-.5 .5 .5v1.1M124.7 216.4v-1.1l.6-.6 .5 .6v1.1M124.7 217.3h.8l.3 .3v1l-.3 .3h-.8zM126.4 219.8v1.6h1M126.4 217.3h.5M126.4 218.9h.5M126.6 217.3v1.6M127.4 212.2v1.6l-1-1.6v1.6M127.4 214.7v1.7l-1-1.7v1.7M127.7 217.3h.6l.2 .3v1l-.2 .3h-.6l-.2-.3v-1z"/>
<path d="M128 215.5h1.1M128 213h1.1M128 219.8v1.6M129.1 219.8l-1.1 1.1M129.6 215.5h1.1M129.6 212.2v1.6h1.1M129.6 214.7v1.7M130.7 214.7v1.7M136.7 205.2v-1.6l.5 .5 .6-.5v1.6M138.3 204.4h1.1M138.3 205.2v-1.1l.6-.5 .5 .5v1.1M140 204.4h.8"/>
<path d="M140 203.6h.8l.3 .2-.3 .6 .3 .5-.3 .3h-.8zM142.7 203.8l-.3-.2h-.5l-.3 .2v1.1l.3 .3h.5l.3-.3M144.3 204.4h-1.1l.9-.8v1.6M145.1 204.4h.6M145.1 204.4l-.2-.3 .2-.5h.6l.3 .2-.3 .6M145.1 204.4l-.2 .2 .2 .6h.6l.3-.3-.3-.5M146.5 204.4h.8M146.5 203.6h.8l.3 .2-.3 .6 .3 .5-.3 .3h-.8zM146.9 205.3l1 1.7M146.9 207.9l1 1.6M146.9 210.4l1 1.6M146.9 213l1 1.6"/>
<path d="M146.9 215.5l1 1.6M146.9 218l1 1.7M147.9 205.3l-1 1.7M147.9 207.9l-1 1.6M147.9 210.4l-1 1.6M147.9 213l-1 1.6M147.9 215.5l-1 1.6M147.9 218l-1 1.7M148.1 203.8l.3-.2h.6l.2 .2v.3l-1.1 1.1h1.1M148.5 207h1.1M148.5 209.5h1.1M148.5 212h1.1"/>
<path d="M148.5 214.6h1.1M148.5 217.1h1.1M148.5 219.7h1.1M148.5 205.9l.5-.6v1.7M148.5 208.4l.5-.5v1.6M148.5 211l.5-.6v1.6M148.5 213.5l.5-.5v1.6M148.5 216l.5-.5v1.6M148.5 218.6l.5-.6v1.7M150.1 206.1h1.1M150.1 208.7h1.1M150.1 211.2h1.1"/>
<path d="M150.1 213.8h1.1M150.1 216.3h1.1M150.1 218.8h1.1M152.8 210.7l-.2-.3h-.6l-.2 .3v1.1l.2 .2h.6l.2-.2M152.8 205.6l-.2-.3h-.6l-.2 .3v1.1l.2 .3h.6l.2-.3M152.8 208.2l-.2-.3h-.6l-.2 .3v1l.2 .3h.6l.2-.3M152.8 213.2l-.2-.2h-.6l-.2 .2v1.1l.2 .3h.6l.2-.3M152.8 215.8l-.2-.3h-.6l-.2 .3v1.1l.2 .2h.6l.2-.2M152.8 218.3l-.2-.3h-.6l-.2 .3v1.1l.2 .3h.6l.2-.3M153.4 210.7l.3-.3h.5l.3 .3-.3 .5M153.4 207h1.1M153.4 208.2l.3-.3h.5l.3 .3v.2l-1.1 1.1h1.1"/>
<path d="M153.4 218.8h.8l.3 .6-.3 .3h-.5l-.3-.3zM153.4 205.9l.5-.6v1.7M153.9 211.2h.3M154.2 211.2l.3 .3-.3 .5h-.5l-.3-.2M154.5 213.8h-1.1l.8-.8v1.6M154.5 215.5h-1.1v.8l.5-.3 .6 .3v.6l-.3 .2h-.5l-.3-.2M154.5 218l-1.1 .8M220.6 219.7l-.3-.3h-.5l-.3 .3v1.1l.3 .3h.5l.3-.3M221.1 219.7l.3-.3h.5l.3 .3-.3 .5M229.2 209.9l-.3-.2h-.5l-.3 .5 .3 .3h.5l.3 .5-.3 .3h-.5l-.3-.3M229.8 209.7h1M230.3 209.7v1.6"/>
<path d="M230.7 219.7l-.2-.3h-.6l-.3 .3v1.1l.3 .3h.6l.2-.3M231.4 209.7h.8l.3 .2-.3 .6 .3 .5-.3 .3h-.8zM231.4 210.5h.8M232.4 219.4l-1.1 .8M233 209.7v.2l.6 .6M233.6 210.5v.8M234.1 209.7v.2l-.5 .6M234.7 209.9l.2-.2h.6l.3 .2-.3 .6M235.2 210.5h.3M235.5 210.5l.3 .2-.3 .6h-.6l-.2-.3M236.3 209.7v1l.6 .6 .5-.6v-1M237.9 209.9l.3-.2h.6l.2 .2-.2 .6"/>
<path d="M238.5 210.5h.3M238.8 210.5l.2 .2-.2 .6h-.6l-.3-.3M240.9 219.7l-.3-.3h-.5l-.3 .3v1.1l.3 .3h.5l.3-.3M241.4 219.4h1.1l-1.1 1.7M63 220.6l1.1 1.6M63 223.1l1.1 1.6M63 225.7l1.1 1.6M63 228.2l1.1 1.6M63 230.7l1.1 1.7M63 233.3l1.1 1.6M63 235.8l1.1 1.6M63 238.4l1.1 1.6"/>
<path d="M64.1 220.6l-1.1 1.6M64.1 223.1l-1.1 1.6M64.1 225.7l-1.1 1.6M64.1 228.2l-1.1 1.6M64.1 230.7l-1.1 1.7M64.1 233.3l-1.1 1.6M64.1 235.8l-1.1 1.6M64.1 238.4l-1.1 1.6M64.7 221.1l.5-.5v1.6M64.7 223.7l.5-.6v1.6M64.7 226.2l.5-.5v1.6M64.7 228.7l.5-.5v1.6"/>
<path d="M64.7 231.3l.5-.6v1.7M64.7 233.8l.5-.5v1.6M64.7 236.3l.5-.5v1.6M64.7 238.9l.5-.5v1.6M64.7 222.2h1.1M64.7 224.7h1.1M64.7 227.3h1.1M64.7 229.8h1.1M64.7 232.4h1.1M64.7 234.9h1.1M64.7 237.4h1.1M64.7 240h1.1"/>
<path d="M66.3 221.4h1.1M66.3 223.9h1.1M66.3 226.5h1.1M66.3 229h1.1M66.3 231.5h1.1M66.3 234.1h1.1M66.3 236.6h1.1M66.3 239.2h1.1M67.9 222.2v-1.1l.6-.5 .5 .5v1.1M67.9 224.7v-1l.6-.6 .5 .6v1M67.9 227.3v-1.1l.6-.5 .5 .5v1.1M67.9 229.8v-1.1l.6-.5 .5 .5v1.1"/>
<path d="M67.9 232.4v-1.1l.6-.6 .5 .6v1.1M67.9 234.9v-1.1l.6-.5 .5 .5v1.1M67.9 237.4v-1.1l.6-.5 .5 .5v1.1M67.9 240v-1.1l.6-.5 .5 .5v1.1M67.9 221.4h1.1M67.9 223.9h1.1M67.9 226.5h1.1M67.9 229h1.1M67.9 231.5h1.1M67.9 234.1h1.1M67.9 236.6h1.1M67.9 239.2h1.1"/>
<path d="M69.6 238.9l.5-.5v1.6M69.6 231.3l.5-.6v1.7M69.6 220.6h1.1l-1.1 1.6M69.6 228.7l.5-.5v1.6M69.6 233.8l.5-.5v1.6M69.6 236.3l.5-.5v1.6M69.6 229.8h1.1M69.6 232.4h1.1M69.6 234.9h1.1M69.6 237.4h1.1M69.6 240h1.1M69.9 223.9l-.3-.2 .3-.6h.5l.3 .3-.3 .5"/>
<path d="M69.9 223.9l-.3 .3 .3 .5h.5l.3-.2-.3-.6M69.9 223.9h.5M70.7 226.5h-.8l-.3-.3 .3-.5h.5l.3 .2v1.1l-.3 .3h-.5l-.3-.3M71.2 233.6l.3-.3h.5l.3 .3v.2l-1.1 1.1h1.1M71.2 236.1l.3-.3h.5l.3 .3-.3 .5M71.2 232.4h1.1M71.2 231.3l.6-.6v1.7M71.8 236.6h.2M72 236.6l.3 .3-.3 .5h-.5l-.3-.2M72.3 228.5v1.1l-.3 .2h-.5l-.3-.2M72.3 228.5l-.3-.3h-.5l-.3 .3v1.1M72.3 228.5l-1.1 1.1"/>
<path d="M72.3 239.2h-1.1l.8-.8v1.6M78.3 239.2v-1.6l.5 .5 .6-.5v1.6M79.4 232.5v1.6l-1.1-1.6v1.6M79.4 235.1v1.6l-1.1-1.6v1.6M80.2 232.5h.5l.3 .3v1.1l-.3 .2h-.5l-.3-.2v-1.1zM80.2 235.1h.5l.3 .2v1.1l-.3 .3h-.5l-.3-.3v-1.1zM80.2 237.6h.5l.3 .3v1.1l-.3 .2h-.5l-.3-.2v-1.1zM81.6 232.5h.8l.2 .3v1.1l-.2 .2h-.8zM81.6 235.1h.8l.2 .2v1.1l-.2 .3h-.8zM81.6 237.6h.8l.2 .3v1.1l-.2 .2h-.8zM83.2 235.9h.5M83.2 233.3h.5"/>
<path d="M83.2 238.4h1.1M84.3 235.1h-1.1v1.6h1.1M84.3 232.5h-1.1v1.6h1.1M84.8 235.9h1.1M84.8 233.3h1.1M84.8 239.2v-1.1l.6-.5 .5 .5v1.1M84.8 238.4h1.1M86.5 234.1v-1.1l.5-.5 .5 .5v1.1M86.5 236.7v-1.1l.5-.5 .5 .5v1.1M86.5 235.9h1M86.5 233.3h1M87.5 237.9l-.2-.3h-.6l-.2 .3v1.1"/>
<path d="M87.5 237.9v1.1l-.2 .2h-.6l-.2-.2M87.5 237.9l-1 1.1M88.1 235.3l.3-.2h.5l.3 .2v.3l-1.1 1.1h1.1M89.2 232.8l-.3-.3h-.5l-.3 .3v1.1M89.2 232.8v1.1l-.3 .2h-.5l-.3-.2M89.2 232.8l-1.1 1.1M103.7 220.6l1.1 1.6M103.7 223.1l1.1 1.6M103.7 225.7l1.1 1.6M103.7 228.2l1.1 1.6M103.7 230.7l1.1 1.7M103.7 233.3l1.1 1.6"/>
<path d="M103.7 235.8l1.1 1.6M103.7 238.4l1.1 1.6M104.8 220.6l-1.1 1.6M104.8 223.1l-1.1 1.6M104.8 225.7l-1.1 1.6M104.8 228.2l-1.1 1.6M104.8 230.7l-1.1 1.7M104.8 233.3l-1.1 1.6M104.8 235.8l-1.1 1.6M104.8 238.4l-1.1 1.6M105.3 222.2h1.1M105.3 224.7h1.1"/>
<path d="M105.3 227.3h1.1M105.3 229.8h1.1M105.3 232.4h1.1M105.3 234.9h1.1M105.3 237.4h1.1M105.3 240h1.1M105.3 221.1l.6-.5v1.6M105.3 223.7l.6-.6v1.6M105.3 226.2l.6-.5v1.6M105.3 228.7l.6-.5v1.6M105.3 231.3l.6-.6v1.7M105.3 233.8l.6-.5v1.6"/>
<path d="M105.3 236.3l.6-.5v1.6M105.3 238.9l.6-.5v1.6M107 221.4h1M107 223.9h1M107 226.5h1M107 229h1M107 231.5h1M107 234.1h1M107 236.6h1M107 239.2h1M108.6 220.6h.8l.3 .3-.3 .5 .3 .5-.3 .3h-.8zM108.6 221.4h.8"/>
<path d="M108.6 223.1h.8l.3 .3-.3 .5 .3 .6-.3 .2h-.8zM108.6 223.9h.8M108.6 225.7h.8l.3 .2-.3 .6 .3 .5-.3 .3h-.8zM108.6 226.5h.8M108.6 228.2h.8l.3 .3-.3 .5 .3 .6-.3 .2h-.8zM108.6 229h.8M108.6 230.7h.8l.3 .3-.3 .5 .3 .6-.3 .3h-.8zM108.6 231.5h.8M108.6 233.3h.8l.3 .3-.3 .5 .3 .5-.3 .3h-.8zM108.6 234.1h.8M108.6 235.8h.8l.3 .3-.3 .5 .3 .6-.3 .2h-.8zM108.6 236.6h.8"/>
<path d="M108.6 238.4h.8l.3 .2-.3 .6 .3 .5-.3 .3h-.8zM108.6 239.2h.8M110.2 220.6h1.1l-1.1 1.6M110.2 229.8h1.1M110.2 232.4h1.1M110.2 234.9h1.1M110.2 237.4h1.1M110.2 240h1.1M110.2 228.7l.6-.5v1.6M110.2 231.3l.6-.6v1.7M110.2 233.8l.6-.5v1.6M110.2 236.3l.6-.5v1.6"/>
<path d="M110.2 238.9l.6-.5v1.6M110.5 223.9l-.3 .3 .3 .5h.5l.3-.2-.3-.6M110.5 223.9h.5M110.5 223.9l-.3-.2 .3-.6h.5l.3 .3-.3 .5M111.3 226.5h-.8l-.3-.3 .3-.5h.5l.3 .2v1.1l-.3 .3h-.5l-.3-.3M111.9 233.6l.2-.3h.6l.2 .3v.2l-1 1.1h1M111.9 232.4h1M111.9 236.1l.2-.3h.6l.2 .3-.2 .5M111.9 231.3l.5-.6v1.7M112.4 236.6h.3M112.7 236.6l.2 .3-.2 .5h-.6l-.2-.2M112.9 228.5v1.1l-.2 .2h-.6l-.2-.2"/>
<path d="M112.9 228.5l-.2-.3h-.6l-.2 .3v1.1M112.9 239.2h-1l.8-.8v1.6M112.9 228.5l-1 1.1M121.5 239.2v-1.6l.5 .5 .5-.5v1.6M121.7 227.4h.6l.2 .3v1.1l-.2 .3h-.6l-.2-.3v-1.1zM121.7 224.9h.6l.2 .3v1.1l-.2 .2h-.6l-.2-.2v-1.1zM122.5 220.1l-.2-.3h-.6l-.2 .6 .2 .2h.6l.2 .6-.2 .2h-.6l-.2-.2M122.5 222.6l-.2-.2h-.6l-.2 .5 .2 .3h.6l.2 .5-.2 .3h-.6l-.2-.3M122.5 232.5v1.6l-1-1.6v1.6M122.5 235.1v1.6l-1-1.6v1.6M123.1 232.8l.3-.3h.5l.3 .3v1.1l-.3 .2h-.5l-.3-.2zM123.1 237.9l.3-.3h.5l.3 .3v1.1l-.3 .2h-.5l-.3-.2z"/>
<path d="M123.1 222.4v1.6l.5-.6 .6 .6v-1.6M123.4 235.1h.5l.3 .2v1.1l-.3 .3h-.5l-.3-.3v-1.1zM124.2 225.2l-.3-.3h-.5l-.3 .3 .3 .5h.5l.3 .3-.3 .5h-.5l-.3-.2M124.2 227.7l-.3-.3h-.5l-.3 .3 .3 .5h.5l.3 .3-.3 .6h-.5l-.3-.3M124.7 235.1h.8l.3 .2v1.1l-.3 .3h-.8zM124.7 222.6l.3-.2h.5l.3 .2v1.1l-.3 .3h-.5l-.3-.3zM124.7 237.6h.8l.3 .3v1.1l-.3 .2h-.8zM124.7 232.5h.8l.3 .3v1.1l-.3 .2h-.8zM125.8 225.2l-.3-.3h-.5l-.3 .3v1.1l.3 .2h.5l.3-.2M125.8 227.7l-.3-.3h-.5l-.3 .3v1.1l.3 .3h.5l.3-.3M125.8 220.1l-.3-.3h-.5l-.3 .3v1.1l.3 .2h.5l.3-.2M126.4 235.9h.5"/>
<path d="M126.4 225.7h1M126.4 228.2h1M126.4 233.3h.5M126.4 238.4h1M127.4 235.1h-1v1.6h1M127.4 232.5h-1v1.6h1M128 235.9h1.1M128 228.2h1.1M128 233.3h1.1M128 238.4h1.1M128 224.9v1.6h1.1M128 227.4v1.7"/>
<path d="M128 239.2v-1.1l.5-.5 .6 .5v1.1M128.3 220.6l.8 .8M129.1 227.4v1.7M129.6 235.9h1.1M129.6 233.3h1.1M129.6 234.1v-1.1l.6-.5 .5 .5v1.1M129.6 236.7v-1.1l.6-.5 .5 .5v1.1M129.6 239.2h1.1M129.6 238.1l.6-.5v1.6M130.7 225.2l-.2-.3h-.6l-.3 .3 .3 .5h.6l.2 .3-.2 .5h-.6l-.3-.2M130.7 227.7l-.2-.3h-.6l-.3 .3 .3 .5h.6l.2 .3-.2 .6h-.6l-.3-.3M131.3 235.3l.3-.2h.5l.3 .2-.3 .6"/>
<path d="M131.3 225.7h.5M131.3 228.2h.5M131.3 234.1h1.1M131.3 233l.5-.5v1.6M131.8 235.9h.3M132.1 235.9l.3 .2-.3 .6h-.5l-.3-.3M132.4 227.4h-1.1v1.7h1.1M132.4 224.9h-1.1v1.6h1.1M146.9 220.6l1 1.6M146.9 223.1l1 1.6M146.9 225.7l1 1.6M146.9 228.2l1 1.6"/>
<path d="M146.9 230.7l1 1.7M146.9 233.3l1 1.6M146.9 235.8l1 1.6M146.9 238.4l1 1.6M147.9 220.6l-1 1.6M147.9 223.1l-1 1.6M147.9 225.7l-1 1.6M147.9 228.2l-1 1.6M147.9 230.7l-1 1.7M147.9 233.3l-1 1.6M147.9 235.8l-1 1.6M147.9 238.4l-1 1.6"/>
<path d="M148.5 223.7l.5-.6v1.6M148.5 222.2h1.1M148.5 224.7h1.1M148.5 227.3h1.1M148.5 229.8h1.1M148.5 232.4h1.1M148.5 234.9h1.1M148.5 237.4h1.1M148.5 240h1.1M148.5 221.1l.5-.5v1.6M148.5 226.2l.5-.5v1.6M148.5 228.7l.5-.5v1.6"/>
<path d="M148.5 231.3l.5-.6v1.7M148.5 233.8l.5-.5v1.6M148.5 236.3l.5-.5v1.6M148.5 238.9l.5-.5v1.6M150.1 221.4h1.1M150.1 223.9h1.1M150.1 226.5h1.1M150.1 229h1.1M150.1 231.5h1.1M150.1 234.1h1.1M150.1 236.6h1.1M150.1 239.2h1.1"/>
<path d="M152.8 220.9l-.2-.3h-.6l-.2 .3v1l.2 .3h.6l.2-.3M152.8 223.4l-.2-.3h-.6l-.2 .3v1.1l.2 .2h.6l.2-.2M152.8 225.9l-.2-.2h-.6l-.2 .2v1.1l.2 .3h.6l.2-.3M152.8 228.5l-.2-.3h-.6l-.2 .3v1.1l.2 .2h.6l.2-.2M152.8 231l-.2-.3h-.6l-.2 .3v1.1l.2 .3h.6l.2-.3M152.8 233.6l-.2-.3h-.6l-.2 .3v1l.2 .3h.6l.2-.3M152.8 236.1l-.2-.3h-.6l-.2 .3v1.1l.2 .2h.6l.2-.2M152.8 238.6l-.2-.2h-.6l-.2 .2v1.1l.2 .3h.6l.2-.3M153.4 220.6h1.1l-1.1 1.6M153.4 229.8h1.1M153.4 232.4h1.1M153.4 234.9h1.1"/>
<path d="M153.4 237.4h1.1M153.4 240h1.1M153.4 228.7l.5-.5v1.6M153.4 231.3l.5-.6v1.7M153.4 233.8l.5-.5v1.6M153.4 236.3l.5-.5v1.6M153.4 238.9l.5-.5v1.6M153.7 223.9l-.3 .3 .3 .5h.5l.3-.2-.3-.6M153.7 223.9h.5M153.7 223.9l-.3-.2 .3-.6h.5l.3 .3-.3 .5M154.5 226.5h-.8l-.3-.3 .3-.5h.5l.3 .2v1.1l-.3 .3h-.5l-.3-.3M155 232.4h1.1"/>
<path d="M155 233.6l.3-.3h.6l.2 .3v.2l-1.1 1.1h1.1M155 236.1l.3-.3h.6l.2 .3-.2 .5M155 231.3l.6-.6v1.7M155.6 236.6h.3M155.9 236.6l.2 .3-.2 .5h-.6l-.3-.2M156.1 228.5v1.1l-.2 .2h-.6l-.3-.2M156.1 228.5l-.2-.3h-.6l-.3 .3v1.1M156.1 239.2h-1.1l.9-.8v1.6M156.1 228.5l-1.1 1.1M219.5 225.1l.5-.6v1.6M219.5 226.1h1.1M221.7 220.2h.2"/>
<path d="M221.9 220.2l.3 .3-.3 .6h-.5l-.3-.3M222.2 224.8v1.1l-.3 .2h-.5l-.3-.2M222.2 224.8l-.3-.3h-.5l-.3 .3v1.1M222.2 224.8l-1.1 1.1M223.8 224.8v1.1l-.2 .2h-.6l-.2-.2M223.8 224.8l-.2-.3h-.6l-.2 .3v1.1M223.8 224.8l-1 1.1M224.4 226.1v-1h.8l.3 .2v.8M226 225.3h.6M226.7 235.3l-.3-.2h-.6l-.2 .2v1.1l.2 .3h.6l.3-.3v-.5h-.6M227.1 224.5h-1.1v1.6M228.3 235.1v1.6l-1.1-1.6v1.6"/>
<path d="M228.9 235.1h.8l.2 .2v1.1l-.2 .3h-.8zM229.6 226.1h1.1M229.6 225.1l.6-.6v1.6M231.3 220.2h.8l.3 .6-.3 .3h-.5l-.3-.3zM232.4 224.8v1.1l-.3 .2h-.5l-.3-.2M232.4 224.8l-.3-.3h-.5l-.3 .3v1.1M232.4 224.8l-1.1 1.1M234 224.8v1.1l-.3 .2h-.5l-.3-.2M234 224.8l-.3-.3h-.5l-.3 .3v1.1M234 224.8l-1.1 1.1M234.5 226.1v-1h.9l.2 .2v.8M236.2 225.3h.5"/>
<path d="M237.3 224.5h-1.1v1.6M239.8 226.1h1.1M239.8 225.1l.5-.6v1.6M242.5 224.8v1.1l-.2 .2h-.6l-.3-.2M242.5 224.8l-.2-.3h-.6l-.3 .3v1.1M242.5 224.8l-1.1 1.1M244.2 224.8v1.1l-.3 .2h-.5l-.3-.2M244.2 224.8l-.3-.3h-.5l-.3 .3v1.1M244.2 224.8l-1.1 1.1M244.7 226.1v-1h.8l.3 .2v.8M246.4 225.3h.5M247.4 224.5h-1v1.6"/>
<path d="M54 248l-.3-.2h-.6l-.2 .2v1.1l.2 .3h.6l.3-.3v-.5h-.6M55.6 247.8v1.6l-1.1-1.6v1.6M56.2 247.8h.8l.2 .2v1.1l-.2 .3h-.8zM63 240.9l1.1 1.6M63 243.4l1.1 1.7M64.1 240.9l-1.1 1.6M64.1 243.4l-1.1 1.7M64.7 241.4l.5-.5v1.6M64.7 244l.5-.6v1.7M64.7 242.5h1.1M64.7 245.1h1.1M66.3 241.7h1.1"/>
<path d="M66.3 244.2h1.1M67.9 242.5v-1.1l.6-.5 .5 .5v1.1M67.9 245.1v-1.1l.6-.6 .5 .6v1.1M67.9 241.7h1.1M67.9 244.2h1.1M69.6 241.4l.5-.5v1.6M69.6 244l.5-.6v1.7M69.6 242.5h1.1M69.6 245.1h1.1M71.2 244.2h.8l.3 .6-.3 .3h-.5l-.3-.3zM72.3 240.9h-1.1v.8l.6-.3 .5 .3v.6l-.3 .2h-.5l-.3-.2M72.3 243.4l-1.1 .8"/>
<path d="M78.3 241.8v-1.7l.5 .6 .6-.6v1.7M80.2 240.1h.5l.3 .3v1.1l-.3 .3h-.5l-.3-.3v-1.1zM81.6 240.1h.8l.2 .3v1.1l-.2 .3h-.8zM83.2 240.9h1.1M84.8 241.8v-1.1l.6-.6 .5 .6v1.1M84.8 240.9h1.1M86.5 240.4l.2-.3h.6l.2 .3v.3l-1 1.1h1M103.7 240.9l1.1 1.6M103.7 243.4l1.1 1.7M104.8 240.9l-1.1 1.6M104.8 243.4l-1.1 1.7M105.3 242.5h1.1"/>
<path d="M105.3 245.1h1.1M105.3 241.4l.6-.5v1.6M105.3 244l.6-.6v1.7M107 241.7h1M107 244.2h1M108.6 240.9h.8l.3 .3-.3 .5 .3 .6-.3 .2h-.8zM108.6 241.7h.8M108.6 243.4h.8l.3 .3-.3 .5 .3 .6-.3 .3h-.8zM108.6 244.2h.8M110.2 242.5h1.1M110.2 245.1h1.1M110.2 241.4l.6-.5v1.6"/>
<path d="M110.2 244l.6-.6v1.7M111.9 244.2h.8l.2 .6-.2 .3h-.6l-.2-.3zM112.9 240.9h-1v.8l.5-.3 .5 .3v.6l-.2 .2h-.6l-.2-.2M112.9 243.4l-1 .8M121.5 241.8v-1.7l.5 .6 .5-.6v1.7M123.1 240.4l.3-.3h.5l.3 .3v1.1l-.3 .3h-.5l-.3-.3zM124.7 240.1h.8l.3 .3v1.1l-.3 .3h-.8zM126.4 240.9h1M128 241.8v-1.1l.5-.6 .6 .6v1.1M128 240.9h1.1M129.6 240.4l.3-.3h.6l.2 .3-.2 .5M130.2 240.9h.3"/>
<path d="M130.5 240.9l.2 .3-.2 .6h-.6l-.3-.3M146.9 240.9l1 1.6M146.9 243.4l1 1.7M147.9 240.9l-1 1.6M147.9 243.4l-1 1.7M148.5 242.5h1.1M148.5 245.1h1.1M148.5 241.4l.5-.5v1.6M148.5 244l.5-.6v1.7M150.1 241.7h1.1M150.1 244.2h1.1M152.8 243.7l-.2-.3h-.6l-.2 .3v1.1l.2 .3h.6l.2-.3"/>
<path d="M152.8 241.2l-.2-.3h-.6l-.2 .3v1.1l.2 .2h.6l.2-.2M153.4 242.5h1.1M153.4 245.1h1.1M153.4 241.4l.5-.5v1.6M153.4 244l.5-.6v1.7M155 244.2h.9l.2 .6-.2 .3h-.6l-.3-.3zM156.1 243.4l-1.1 .8M156.1 240.9h-1.1v.8l.6-.3 .5 .3v.6l-.2 .2h-.6l-.3-.2"/>
</g>
<g fill="none" stroke="#800000" stroke-width=".31">
<path d="M26.1 10.7h379.7v252.7h-379.7zM48.8 8.4l.8-.8v2.4M48.8 10h1.6M73.6 6.9v3.8M96.2 8l.4-.4h.8l.4 .4v.4l-1.6 1.6h1.6M121.1 6.9v3.8M129 18.4l1.3 1.9M129 18.4l-1.3 1.9M129 18.4v2.5M143.7 8l.4-.4h.8l.4 .4v.4l-.4 .4M144.5 8.8h.4M144.9 8.8l.4 .4v.4l-.4 .4h-.8l-.4-.4"/>
<path d="M168.5 6.9v3.8M192.8 8.8h-1.6l1.2-1.2v2.4M216 6.9v3.8M240.2 7.6h-1.6v1.2l.8-.4h.4l.4 .4v.8l-.4 .4h-.8l-.4-.4M263.4 6.9v3.8M286.1 8.8h1.2l.4 .4v.4l-.4 .4h-.8l-.4-.4zM287.7 7.6l-.8 .4-.8 .8M310.9 6.9v3.8M333.5 7.6h1.6v.4l-1.6 1.6v.4M358.4 6.9v3.8M381.4 8.8l-.4-.4v-.4l.4-.4h.8l.4 .4v.4l-.4 .4M381.4 8.8l-.4 .4v.4l.4 .4h.8l.4-.4v-.4l-.4-.4"/>
<path d="M381.4 8.8h.8M23.1 37.2v-1.6l.8-.8 .8 .8v1.6M23.1 36h1.6M73.1 33.6h5.1M103.6 33.6h5.1M235.7 38.7h2.5M322 38.7h5.1M352.5 38.7h5.1M406.6 36h1.6M406.6 37.2v-1.6l.8-.8 .8 .8v1.6M73.1 43.8h5.1M73.1 53.9h5.1"/>
<path d="M103.6 53.9h5.1M103.6 51.4h5.1M115.4 43.8h1.8v5h-1.8zM116.3 41.2v2.6M116.3 48.8v2.6M210.9 56.5h3.8M212.8 43.8v3M212.8 48.3v3.1M212.8 53.9v2.6M223 41.2h2.5M228.7 56.5h3.8M230.6 46.3v2.5"/>
<path d="M230.6 53.9v2.6M235.7 41.2h2.5M292.2 59h3.8M293.2 48.8h1.8v5.1h-1.8zM294.1 46.3v2.5M294.1 53.9v5.1M302.3 59h3.8M304.2 46.3v3M304.2 50.9v3M304.2 56.5v2.5M312.5 59h3.8M314.4 56.5v2.5"/>
<path d="M322 43.8h5.1M322 51.4h5.1M322 46.3h5.1M352.5 48.8h5.1M352.5 46.3h5.1M352.5 41.2h5.1M22.3 61.3h3.8M57 64.1h1.8v5.1h-1.8zM57.9 61.5v2.6M57.9 69.2v2.5M73.1 69.2v3M73.1 73.7v3.1"/>
<path d="M129 69.2v3M129 73.7v3.1M324.6 70v1.6h1.1M326.3 70.8h1M329 70.3l-.3-.3h-.5l-.3 .3v1l.3 .3h.5l.3-.3M329.5 70.8h1.1M329.5 71.6v-1.1l.6-.5 .5 .5v1.1M332.3 70v1.6l-1.1-1.6v1.6M334.5 70.5h.5M334.7 70.3v1l.3 .3M335.5 70.5v1.1M336.4 70.5l-.9 .6"/>
<path d="M337.2 70.5h.5l.3 .3v.8h-.8l-.3-.3 .3-.2h.8M338.5 71.6v-1.1h.9l.2 .3v.8M341.3 70.5h-.9l-.2 .3 .2 .3h.6l.3 .2-.3 .3h-.8M342.9 70.5h-.8l-.3 .3v.5l.3 .3h.8M343.5 71.1h1.1l-.3-.6h-.6l-.2 .3v.5l.2 .3h.6M345.1 71.6h.5M345.1 70.5h.3v1.1M345.4 69.7v.3M346.2 70.5l.5 1.1 .6-1.1M347.8 71.1h1.1l-.3-.6h-.5l-.3 .3v.5l.3 .3h.5M349.5 70.5v1.1M350.3 70.5l-.8 .6"/>
<path d="M405.8 61.3h3.8M23.1 85.3h1.2l.4 .4v.4l-.4 .4 .4 .4v.4l-.4 .4h-1.2zM23.1 86.5h1.2M56 84.4h3.8M57.9 81.9v2.5M63.6 84.4h3.8M65.5 81.9v2.5M71.2 84.4h3.8M73.1 81.9v2.5M83.3 97.1l1.3 1.9M83.3 97.1l-1.3 1.9M83.3 97.1v2.5"/>
<path d="M106.2 97.1v2.5M106.2 97.1l1.2 1.9M106.2 97.1l-1.3 1.9M127.1 84.4h3.8M129 81.9v2.5M327.1 89.5l1.3 1.9M327.1 89.5l-1.3 1.9M327.1 89.5v2.5M337.2 99.6h2.6M339.8 98.7h5.1v1.8h-5.1zM344.9 99.6h2.5M352.5 99.6h7.6"/>
<path d="M355 98.3l2.6 1.3-2.6 1.3zM357.6 98.3v2.6M406.6 85.3h1.2l.4 .4v.4l-.4 .4 .4 .4v.4l-.4 .4h-1.2zM406.6 86.5h1.2M22.3 111.8h3.8M70.6 119.9l1.3 1.9M70.6 119.9l-1.3 1.9M70.6 119.9v2.6M85.8 104.7h5.1M85.8 107.2h5.1M85.8 109.8h5.1M85.8 112.3h5.1"/>
<path d="M85.8 114.9h5.1M85.8 117.4h5.1M85.8 119.9h5.1M96 104.7h5.1M96 107.2h5.1M96 109.8h5.1M96 112.3h5.1M96 114.9h5.1M96 117.4h5.1M96 119.9h5.1M113.7 119.9l1.3 1.9M113.7 119.9l-1.2 1.9"/>
<path d="M113.7 119.9v2.6M196.7 112.3h1.8v5.1h-1.8zM197.6 109.8v2.5M197.6 117.4v2.5M217.9 119.9v2.6M220.4 119.9v2.6M223 119.9v2.6M225.5 119.9v2.6M228 119.9v2.6M230.6 119.9v2.6M233.1 119.9v2.6M235.7 119.9v2.6"/>
<path d="M238.2 119.9v2.6M240.7 119.9v2.6M243.3 119.9v2.6M245.8 119.9v2.6M337.2 109.8h2.6M337.2 119.9h2.6M339.8 108.9h5.1v1.8h-5.1zM339.8 119h5.1v1.8h-5.1zM344.9 109.8h2.5M344.9 119.9h2.5M350 101.5h.8l.3-.2v-.6l-.3-.2h-.8v1.6M350.6 101.5l.5 .6"/>
<path d="M351.1 110.9l-.3-.3h-.5l-.3 .3v1.1l.3 .2h.5l.3-.2v-.6h-.5M351.7 111.7h.8l.2-.3v-.5l-.2-.3h-.8v1.6M351.7 101.3h.5M352.2 111.7l.5 .5M352.5 109.8h7.6M352.5 119.9h7.6M352.7 100.5h-1v1.6h1M353.3 100.5h.8l.3 .2v1.1l-.3 .3h-.8zM354.4 110.6v1.6l-1.1-1.6v1.6M355 108.5l2.6 1.3-2.6 1.2zM355 118.7l2.6 1.2-2.6 1.3zM355.8 101.6l1.4 1.4"/>
<path d="M355.8 111.8l1.4 1.4M356.3 102.7l.5-.5 .4 .8zM356.3 112.8l.9 .4M356.3 112.8h.7M356.4 102.7h.6M356.4 102.6h.6M356.4 112.7h.6M356.5 102.4h.4M356.5 112.6h.4M356.6 112.9h.5M356.6 102.3h.3M356.7 102.8h.4"/>
<path d="M356.7 112.5h.2M356.8 102.2h.1M356.8 112.4h.1M356.8 112.3l-.5 .5M356.8 112.3l.4 .9M356.9 113.1h.2M356.9 101.5l1.4 1.4M356.9 102.9h.2M356.9 111.7l1.4 1.4M357.1 113.2h.1M357.4 112.7l.9 .4M357.5 112.7h.7"/>
<path d="M357.5 102.6h.7M357.5 102.4h.6M357.5 112.6h.6M357.6 108.5v2.5M357.6 118.7v2.5M357.7 102.3h.4M357.7 112.5h.4M357.8 112.8h.4M357.8 102.2h.2M357.8 112.4h.2M357.8 102.7h.4M357.9 102.1h.1"/>
<path d="M357.9 112.2h.1M357.9 102l.4 .9-.9-.4zM357.9 112.2l-.5 .5M357.9 112.2l.4 .9M358 112.9h.3M358.1 102.8h.2M358.3 113.1h.1M405.8 111.8h3.8M24.7 136.3l-.4-.4h-.8l-.4 .4v1.6l.4 .4h.8l.4-.4M69.7 127.6h1.8v5h-1.8zM70.6 125v2.6M70.6 132.6v2.6"/>
<path d="M85.8 122.5h5.1M85.8 125h5.1M85.8 127.6h5.1M85.8 130.1h5.1M85.8 132.6h5.1M85.8 135.2h5.1M85.8 137.7h5.1M96 122.5h5.1M96 125h5.1M96 127.6h5.1M96 130.1h5.1M96 132.6h5.1"/>
<path d="M96 135.2h5.1M96 137.7h5.1M112.9 127.6h1.7v5h-1.7zM113.7 125v2.6M113.7 132.6v2.6M212.8 125h2.5M212.8 127.6h2.5M212.8 130.1h2.5M212.8 132.6h2.5M212.8 135.2h2.5M212.8 137.7h2.5M215.3 122.5h33.1v33h-33.1z"/>
<path d="M248.4 125h2.5M248.4 127.6h2.5M248.4 130.1h2.5M248.4 132.6h2.5M248.4 135.2h2.5M248.4 137.7h2.5M337.2 130.1h2.6M339.8 129.2h5.1v1.8h-5.1zM344.9 130.1h2.5M350 120.8l.6 .8M350 130.9h.8l.3 .3-.3 .5 .3 .6-.3 .3h-.8zM350 131.7h.8"/>
<path d="M350.6 121.6v.8M351.1 120.8v.3l-.5 .5M351.7 130.9v1.7h1M351.7 121.6h.5M352.5 130.1h7.6M352.7 120.8h-1v1.6h1M353.3 120.8v1.6h1.1M353.3 130.9v1.4l.3 .3h.5l.3-.3v-1.4M355 128.8l2.6 1.3-2.6 1.3zM355.8 122l1.4 1.4M355.8 132.1l1.4 1.4M356.3 123l.9 .4"/>
<path d="M356.3 133.1l.5-.5 .4 .9zM356.3 123h.7M356.3 133.1h.7M356.4 122.8h.6M356.5 133.2h.6M356.5 133h.5M356.5 123.1h.6M356.6 122.7h.3M356.6 132.8h.3M356.7 122.6h.2M356.7 132.7h.1M356.8 133.3h.3"/>
<path d="M356.8 122.5h.1M356.8 122.5l-.5 .5M356.8 122.5l.4 .9M356.8 123.2h.3M356.9 121.8l1.4 1.4M356.9 132l1.4 1.4M357 133.5h.2M357.1 123.3h.1M357.4 122.9l.9 .3M357.5 122.8h.7M357.5 133h.7M357.6 128.8v2.6"/>
<path d="M357.6 122.7h.5M357.6 132.8h.5M357.6 133.1h.6M357.7 123h.5M357.7 122.6h.4M357.7 132.7h.4M357.8 122.5h.2M357.8 132.6h.2M357.9 133.2h.3M357.9 122.3l-.5 .6M357.9 122.3l.4 .9M357.9 122.4h.1"/>
<path d="M357.9 132.5l.4 .9-.9-.4zM358 123.1h.3M358.2 133.3h.1M358.2 123.2h.1M365.2 137.7v2.6M408.2 136.3l-.4-.4h-.8l-.4 .4v1.6l.4 .4h.8l.4-.4M78.8 158h3.9M80.8 155.5v2.5M85.8 140.3h5.1M85.8 142.8h5.1M85.8 145.3h5.1M85.8 147.9h5.1"/>
<path d="M85.8 150.4h5.1M85.8 153h5.1M96 140.3h5.1M96 142.8h5.1M96 145.3h5.1M96 147.9h5.1M96 150.4h5.1M96 153h5.1M104.2 158h3.9M106.2 155.5v2.5M212.8 140.3h2.5M212.8 142.8h2.5"/>
<path d="M212.8 145.3h2.5M212.8 147.9h2.5M212.8 150.4h2.5M212.8 153h2.5M217.9 155.5v2.5M220.4 155.5v2.5M223 155.5v2.5M225.5 155.5v2.5M228 155.5v2.5M230.6 155.5v2.5M233.1 155.5v2.5M235.7 155.5v2.5"/>
<path d="M238.2 155.5v2.5M240.7 155.5v2.5M243.3 155.5v2.5M245.8 155.5v2.5M248.4 140.3h2.5M248.4 142.8h2.5M248.4 145.3h2.5M248.4 147.9h2.5M248.4 150.4h2.5M248.4 153h2.5M363.3 140.3h3.8M22.3 162.3h3.8"/>
<path d="M234.8 178.4h1.8v5h-1.8zM235.7 175.8v2.6M265.3 175.8h1.7v5.1h-1.7zM266.1 173.3v2.5M405.8 162.3h3.8M23.1 186.4h1.2l.4 .4v1.6l-.4 .4h-1.2zM60.4 193.6h10.2M60.5 187.1l.3-.3h.5l.3 .3v.2l-1.1 1.1h1.1M61.7 192.8h7.6v1.6h-7.6zM62.1 188.2h.3v.2h-.3zM64.1 186.8h-1.2v.8l.6-.3 .6 .3v.6l-.3 .2h-.6l-.3-.2M64.6 188.4v-1.1l.5-.5 .6 .5v1.1"/>
<path d="M64.6 187.6h1.1M67.9 187.9h.8l.3-.3v-.5l-.3-.3h-.8v1.6M69.5 186.8h1.1M70 186.8v1.6M72.2 187.1l-.2-.3h-.6l-.3 .3v1.1l.3 .2h.6l.2-.2M205.8 191.1h3.8M207.7 188.5v2.6M229.2 199.8l-.3-.3h-.5l-.3 .5 .3 .3h.5l.3 .6-.3 .2h-.5l-.3-.2M229.8 199.5h1M230.3 199.5v1.6M233 199.8l.3-.3h.5l.3 .3-.3 .5M233.8 191.1h3.8"/>
<path d="M234.7 199.8l.2-.3h.6l.3 .3v.2l-1.1 1.1h1.1M235.7 183.4v2.6M235.7 188.5v2.6M237.4 199.5h-1.1v1.6M240.7 199.8l-.3-.3h-.5l-.3 .3v1.1M240.7 199.8v1.1l-.3 .2h-.5l-.3-.2M240.7 199.8l-1.1 1.1M241.2 199.8l.3-.3h.5l.3 .3-.3 .5M241.4 191.1h3.8M243.3 188.5v2.6M243.9 199.8l-.2-.3h-.6l-.3 .3v1.1l.3 .2h.6l.2-.2M246.1 199.5h1.1"/>
<path d="M246.7 199.5v1.6M248.9 199.5l-1.1 .8M259.2 191.1h3.8M261.1 188.5v2.6M264.2 191.1h3.9M266.1 180.9v2.5M266.1 188.5v2.6M406.6 186.4h1.2l.4 .4v1.6l-.4 .4h-1.2zM22.3 212.9h3.8M57.9 206.3h2.5M57.9 208.8h2.5M57.9 211.3h2.5"/>
<path d="M57.9 213.9h2.5M57.9 216.4h2.5M57.9 219h2.5M98.5 206.3h2.6M98.5 208.8h2.6M98.5 211.3h2.6M98.5 213.9h2.6M98.5 216.4h2.6M98.5 219h2.6M141.7 206.3h2.5M141.7 208.8h2.5M141.7 211.3h2.5"/>
<path d="M141.7 213.9h2.5M141.7 216.4h2.5M141.7 219h2.5M217.9 219v3M228 219v3M231.4 201.1v-1.6l.5 .5 .6-.5v1.6M233.6 200.3h.2M233.8 200.3l.3 .3-.3 .5h-.5l-.3-.2M236.3 200.3h.6M237.9 201.1h1.1M237.9 200l.6-.5v1.6M238.2 219v3"/>
<path d="M241.8 200.3h.2M242 200.3l.3 .3-.3 .5h-.5l-.3-.2M244.8 200.3l-.3-.3 .3-.5h.5l.3 .3-.3 .5M244.8 200.3h.5M244.8 200.3l-.3 .3 .3 .5h.5l.3-.2-.3-.6M247.8 200.3h.8l.3 .6-.3 .2h-.6l-.2-.2zM405.8 212.9h3.8M23.1 238.1h.8M24.7 236.9h-1.6v2.5h1.6M57.9 239.3h2.5M57.9 221.5h2.5M57.9 224h2.5"/>
<path d="M57.9 226.6h2.5M57.9 229.1h2.5M57.9 231.7h2.5M57.9 234.2h2.5M57.9 236.7h2.5M98.5 239.3h2.6M98.5 221.5h2.6M98.5 224h2.6M98.5 226.6h2.6M98.5 229.1h2.6M98.5 231.7h2.6M98.5 234.2h2.6"/>
<path d="M98.5 236.7h2.6M141.7 239.3h2.5M141.7 221.5h2.5M141.7 224h2.5M141.7 226.6h2.5M141.7 229.1h2.5M141.7 231.7h2.5M141.7 234.2h2.5M141.7 236.7h2.5M217.9 223.5v3.1M226.1 234.2h3.9M228 223.5v3.1"/>
<path d="M228 231.7v2.5M238.2 223.5v3.1M406.6 238.1h.8M408.2 236.9h-1.6v2.5h1.6M53.4 246.9h3.9M55.4 244.4v2.5M57.9 241.8h2.5M57.9 244.4h2.5M98.5 241.8h2.6M98.5 244.4h2.6M141.7 241.8h2.5M141.7 244.4h2.5"/>
<path d="M312 248.6h1.1l.4-.4v-.8l-.4-.4h-1.1v2.3M312.7 248.6l.8 .7M313.5 252.5l-.4-.4h-.7l-.4 .4v1.5l.4 .4h.7l.4-.4M314.3 253.3l.4-.4h.8l.3 .4v.7l-.3 .4h-.8l-.4-.4zM314.7 247.8h.8l.3 .4v1.1h-1.1l-.4-.3 .4-.4h1.1M317.4 253.3l-.4-.4h-.4v1.5M317.4 253.3v1.1M317.4 253.3l.4-.4 .4 .4v1.1M318.2 247.8h-1.2l-.4 .4 .4 .4h.8l.4 .4-.4 .3h-1.2M319 249.3h1.1l.4-.3v-.8l-.4-.4h-1.1v2.3M319 254.4h1.1l.4-.4v-.7l-.4-.4h-1.1v2.3M321.3 247v2.3h1.2l.4-.3v-.8l-.4-.4h-1.2"/>
<path d="M321.3 252.9v1.1l.4 .4h1.2v-1.5M323.7 248.6h1.5v-.4l-.4-.4h-.8l-.3 .4v.8l.3 .3h.8M323.7 252.9h.7M324 252.5v1.5l.4 .4M325.2 253.6h1.6v-.3l-.4-.4h-.8l-.4 .4v.7l.4 .4h.8M326 247.8v1.5M327.2 247.8h-.4l-.8 .8M327.9 247.8v1.5M329.1 247.8h-.4l-.8 .8M329.9 247.8v1.2l.4 .3h1.1M329.9 252.1h1.1l.4 .4v.4l-.4 .4 .4 .3v.4l-.4 .4h-1.1zM329.9 253.3h1.1"/>
<path d="M331.4 247.8v1.9l-.4 .4h-.3M332.2 253.3l.4-.4h.8l.4 .4v.7l-.4 .4h-.8l-.4-.4zM334.6 248.6h1.1l.4-.4v-.8l-.4-.4h-1.1v2.3M335 252.9h.7l.4 .4v1.1h-1.1l-.4-.4 .4-.4h1.1M336.9 247.8h.4v1.5M336.9 249.3h.8M336.9 252.9v1.5M337.3 246.6v.4M338.1 252.9h-.4l-.8 .7M340.4 252.1v2.3h-1.2l-.3-.4v-.7l.3-.4h1.2M343.5 252.1v1.5l.8 .8 .8-.8v-1.5M345.9 252.5l.4-.4h.7l.4 .4v.4l-1.5 1.5h1.5"/>
<path d="M364.6 253.3h41.2M364.6 258.3h41.2M364.6 243.1v20.3M364.6 248.2h41.2M368 255.9h-1.5l1.1-1v2.1M368.1 249.6v2.3h-1.2l-.3-.4v-.8l.3-.4h1.2M368.6 259.8v2.4M369.3 250.3h.8l.4 .4v1.2h-1.2l-.4-.4 .4-.4h1.2M370.1 254.9l-1.4 2.1M370.8 255.6l.7-.7v2.1M370.8 257h1.4M371.2 250.3v1.2l.4 .4h1.2v-1.6"/>
<path d="M372.9 254.9h1.4v.3l-1.4 1.4v.4M375.1 251.9h-1.1l-.4-.4v-.8l.4-.4h1.1v2l-.3 .4h-.4M375.9 250.7l.4-.4h.8l.4 .4v1.2M375.9 249.6v2.3M376.4 254.9l-1.4 2.1M377.1 257h1.4M377.1 255.6l.7-.7v2.1M378.2 250.3h.8M378.7 249.9v1.6l.3 .4M379.2 254.9h1.4v.3l-1.4 1.4v.4M379.8 251.1h1.6v-.4l-.4-.4h-.8l-.4 .4v.8l.4 .4h.8M382.1 250.3v1.6"/>
<path d="M383.3 250.3h-.4l-.8 .8M383.4 257h1.4M383.4 255.6l.7-.7v2.1M383.8 259.7l-1.6 2.3M386.9 255.2v1.4l-.4 .4h-.7l-.3-.4M386.9 255.2l-.4-.3h-.7l-.3 .3v1.4M386.9 255.2l-1.4 1.4M387.6 255.6h.3v.3h-.3zM387.6 256.6h.3v.4h-.3zM390.1 255.2v1.4l-.4 .4h-.7l-.4-.4M390.1 255.2l-.4-.3h-.7l-.4 .3v1.4M390.1 255.2l-1.5 1.4"/>
<path d="M392.2 255.2v1.4l-.4 .4h-.7l-.3-.4M392.2 255.2l-.4-.3h-.7l-.3 .3v1.4M392.2 255.2l-1.4 1.4M395 255.9h1.4M395 257v-1.4l.7-.7 .7 .7v1.4M395.7 258.3v5.1M397.1 257v-2.1l.7 .7 .7-.7v2.1M405.8 243.1h-95.2v20.3M48.8 264.9l.8-.8v2.4M48.8 266.5h1.6M73.6 263.4v3.8M96.2 264.5l.4-.4h.8l.4 .4v.4l-1.6 1.6h1.6"/>
<path d="M121.1 263.4v3.8M143.7 264.5l.4-.4h.8l.4 .4v.4l-.4 .4M144.5 265.3h.4M144.9 265.3l.4 .4v.4l-.4 .4h-.8l-.4-.4M168.5 263.4v3.8M192.8 265.3h-1.6l1.2-1.2v2.4M216 263.4v3.8M240.2 264.1h-1.6v1.2l.8-.4h.4l.4 .4v.8l-.4 .4h-.8l-.4-.4M263.4 263.4v3.8M286.1 265.3h1.2l.4 .4v.4l-.4 .4h-.8l-.4-.4zM287.7 264.1l-.8 .4-.8 .8M310.9 263.4v3.8"/>
<path d="M333.5 264.1h1.6v.4l-1.6 1.6v.4M358.4 263.4v3.8M367.9 260.2l-.4-.4h-.8l-.4 .4v.4l.4 .4h.8l.4 .4v.4l-.4 .4h-.8l-.4-.4M368.6 261l.4-.4h.8l.4 .4v1.2M371 261.4h1.5v-.4l-.3-.4h-.8l-.4 .4v.8l.4 .4h.8M373.3 261.4h1.6v-.4l-.4-.4h-.8l-.4 .4v.8l.4 .4h.8M375.7 260.6h.7M376 260.2v1.6l.4 .4M377.2 260.6h.4v.4h-.4zM377.2 261.8h.4v.4h-.4zM379.9 260.5l.8-.8v2.3M379.9 262h1.5"/>
<path d="M381.4 265.3l-.4 .4v.4l.4 .4h.8l.4-.4v-.4l-.4-.4M381.4 265.3l-.4-.4v-.4l.4-.4h.8l.4 .4v.4l-.4 .4M381.4 265.3h.8M384.6 262h1.5M384.6 260.5l.8-.8v2.3"/>
</g>
<path d="M78.2 31.1h25.4v25.4h-25.4zM225.5 36.1h10.2v10.2h-10.2zM327.1 33.6h25.4v22.9h-25.4zM89.6 102.2h7.7v53.3h-7.7z" fill="none" stroke="#800000" stroke-width=".42"/>
<g fill="none" stroke="#800000" stroke-width=".61">
<path d="M90.9 109.8h1.3M90.9 107.2h1.3M90.9 104.7h1.3M90.9 114.9h1.3M90.9 112.3h1.3M90.9 119.9h1.3M90.9 117.4h1.3M94.7 109.8h1.3M94.7 107.2h1.3M94.7 104.7h1.3M94.7 114.9h1.3M94.7 112.3h1.3"/>
<path d="M94.7 119.9h1.3M94.7 117.4h1.3M90.9 122.5h1.3M90.9 127.6h1.3M90.9 125h1.3M90.9 135.2h1.3M90.9 132.6h1.3M90.9 130.1h1.3M90.9 137.7h1.3M94.7 122.5h1.3M94.7 127.6h1.3M94.7 125h1.3"/>
<path d="M94.7 135.2h1.3M94.7 132.6h1.3M94.7 130.1h1.3M94.7 137.7h1.3M90.9 140.3h1.3M90.9 145.3h1.3M90.9 142.8h1.3M90.9 147.9h1.3M90.9 150.4h1.3M90.9 153h1.3M94.7 140.3h1.3M94.7 145.3h1.3"/>
<path d="M94.7 142.8h1.3M94.7 147.9h1.3M94.7 150.4h1.3M94.7 153h1.3M60.4 206.3h1.3M60.4 208.8h1.3M60.4 211.3h1.3M60.4 213.9h1.3M60.4 216.4h1.3M60.4 219h1.3M101.1 206.3h1.2M101.1 208.8h1.2"/>
<path d="M101.1 211.3h1.2M101.1 213.9h1.2M101.1 216.4h1.2M101.1 219h1.2M144.2 206.3h1.3M144.2 208.8h1.3M144.2 211.3h1.3M144.2 213.9h1.3M144.2 216.4h1.3M144.2 219h1.3M60.4 221.5h1.3M60.4 224h1.3"/>
<path d="M60.4 226.6h1.3M60.4 229.1h1.3M60.4 231.7h1.3M60.4 234.2h1.3M60.4 236.7h1.3M60.4 239.3h1.3M101.1 221.5h1.2M101.1 224h1.2M101.1 226.6h1.2M101.1 229.1h1.2M101.1 231.7h1.2M101.1 234.2h1.2"/>
<path d="M101.1 236.7h1.2M101.1 239.3h1.2M144.2 221.5h1.3M144.2 224h1.3M144.2 226.6h1.3M144.2 229.1h1.3M144.2 231.7h1.3M144.2 234.2h1.3M144.2 236.7h1.3M144.2 239.3h1.3M60.4 241.8h1.3M60.4 244.4h1.3"/>
<path d="M101.1 241.8h1.2M101.1 244.4h1.2M144.2 241.8h1.3M144.2 244.4h1.3"/>
</g>
<path d="M22.3 6.9h387.3v260.3h-387.3z" fill="none" stroke="#800000" stroke-width=".32"/>
<g fill="#800000" stroke="#800000" stroke-width=".31">
<path d="M71.1 73.2h4.1v.5h-4.1z"/>
<path d="M71.1 72.2h4.1v.5h-4.1z"/>
<path d="M127 73.2h4v.5h-4z"/>
<path d="M127 72.2h4v.5h-4z"/>
<path d="M302.2 50.4h4.1v.5h-4.1z"/>
<path d="M302.2 49.3h4.1v.5h-4.1z"/>
<path d="M215.9 223h4v.5h-4z"/>
<path d="M215.9 222h4v.5h-4z"/>
<path d="M226 223h4.1v.5h-4.1z"/>
<path d="M226 222h4.1v.5h-4.1z"/>
<path d="M236.2 223h4v.5h-4z"/>
<path d="M236.2 222h4v.5h-4z"/>
<path d="M210.8 47.8h4v.5h-4z"/>
<path d="M210.8 46.8h4v.5h-4z"/>
</g>
<g fill="none" stroke="#008000" stroke-width=".31">
<path d="M73.1 33.6h-7.6v48.3M108.7 33.6h7.6v7.6M129 20.9v48.3M238.2 38.7h5.1v2.5M289 38.7h33M304.2 38.7v7.6M357.6 38.7h2.5v27.9h-71.1M42.7 53.9h35.5M42.7 43.8h30.4M57.9 43.8v17.7M73.1 53.9v15.3M108.7 51.4h20.3"/>
<path d="M108.7 53.9h20.3M116.3 51.4v12.7h-43.2M197.6 41.2h25.4M212.8 41.2v2.6M212.8 51.4v2.5M230.6 48.8v5.1M238.2 41.2h20.3M289 43.8h33M294.1 46.3h27.9M304.2 53.9v2.6M322 51.4h-7.6v5.1M357.6 48.8h25.4"/>
<path d="M357.6 46.3h25.4M57.9 71.7v10.2M73.1 76.8v5.1M129 76.8v5.1M83.3 99.6v25.4h2.5M106.2 99.6v7.6h-5.1M197.6 94.5v15.3M202.6 94.5v50.8h10.2M217.9 94.5v25.4M268.7 94.5v66.1h-22.9v-2.6M327.1 92v7.6h10.1M347.4 99.6h5.1"/>
<path d="M360.1 99.6h5.1v38.1M60.4 109.8h25.4M60.4 107.2h25.4M83.3 104.7h2.5M88.4 114.9h-7.6v40.6M101.1 109.8h5.1v45.7M101.1 119.9h5.1M101.1 114.9h27.9M101.1 104.7h5.1M101.1 112.3h27.9M174.7 107.2h61v12.7M174.7 102.2h48.3v17.7"/>
<path d="M197.6 119.9v20.4M220.4 119.9v-10.1h-12.7v78.7M228 119.9v-10.1h38.1v63.5M281.4 114.9h-40.7v5M281.4 102.2h-50.8v17.7M281.4 117.4h-17.8v12.7h-12.7M281.4 104.7h-48.3v15.2M281.4 112.3h-35.6v7.6M316.9 109.8h20.3M316.9 119.9h20.3M347.4 109.8h5.1M347.4 119.9h5.1"/>
<path d="M360.1 109.8h5.1M360.1 119.9h5.1M60.4 137.7h25.4M70.6 122.5v2.5M70.6 135.2v2.5M80.8 135.2h5M101.1 127.6h5.1M101.1 137.7h27.9M113.7 122.5v2.5M113.7 135.2v2.5M174.7 135.2h38.1M174.7 130.1h38.1"/>
<path d="M202.6 125h10.2M250.9 127.6h10.2v60.9M250.9 135.2h30.5M250.9 125h17.8M250.9 137.7h30.5M250.9 132.6h30.5M316.9 130.1h20.3M347.4 130.1h5.1M360.1 130.1h5.1M60.4 150.4h25.4M80.8 153h5M101.1 140.3h5.1"/>
<path d="M101.1 145.3h5.1M101.1 150.4h27.9M174.7 140.3h38.1M174.7 153h38.1M174.7 150.4h38.1M174.7 147.9h38.1M207.7 142.8h5.1M217.9 158v2.6h-43.2M220.4 158v7.7h-45.7M223 158v10.2h-48.3M225.5 158v12.7h-50.8M228 158v15.3h-53.3"/>
<path d="M235.7 158v17.8M238.2 158v15.3h45.7M240.7 158v12.7h43.2M243.3 158v30.5M250.9 140.3h30.5M250.9 145.3h30.5M250.9 153h33M250.9 150.4h30.5M250.9 147.9h30.5M60.4 193.6h-12.7v12.7h94M70.6 193.6h30.5M235.7 186v2.5"/>
<path d="M266.1 183.4v5.1M121.4 216.4h20.3M121.4 213.9h20.3M121.4 219h20.3M217.9 219v-2.6h20.3v2.6M228 208.8v10.2M78.2 234.2h20.3M78.2 236.7h20.3M78.2 239.3h20.3M121.4 229.1h20.3M121.4 234.2h20.3M121.4 236.7h20.3"/>
<path d="M121.4 239.3h20.3M121.4 226.6h20.3M121.4 221.5h20.3M121.4 224h20.3M217.9 226.6v2.5h20.3v-2.5M228 226.6v5.1M55.4 244.4h86.3M78.2 241.8h20.3M121.4 241.8h20.3"/>
</g>
<g fill="#008000" stroke="#008000" stroke-width=".31">
<circle cx="106.2" cy="119.9" r=".51"/>
<circle cx="106.2" cy="127.6" r=".51"/>
<circle cx="106.2" cy="140.3" r=".51"/>
<circle cx="106.2" cy="145.3" r=".51"/>
<circle cx="80.8" cy="135.2" r=".51"/>
<circle cx="80.8" cy="153" r=".51"/>
<circle cx="207.7" cy="142.8" r=".51"/>
<circle cx="228" cy="229.1" r=".51"/>
<circle cx="365.2" cy="109.8" r=".51"/>
<circle cx="365.2" cy="119.9" r=".51"/>
<circle cx="365.2" cy="130.1" r=".51"/>
<circle cx="83.3" cy="104.7" r=".51"/>
<circle cx="113.7" cy="137.7" r=".51"/>
<circle cx="70.6" cy="137.7" r=".51"/>
<circle cx="106.2" cy="104.7" r=".51"/>
<circle cx="129" cy="51.4" r=".51"/>
<circle cx="129" cy="53.9" r=".51"/>
<circle cx="73.1" cy="53.9" r=".51"/>
<circle cx="73.1" cy="64.1" r=".51"/>
<circle cx="304.2" cy="38.7" r=".51"/>
<circle cx="212.8" cy="41.2" r=".51"/>
<circle cx="243.3" cy="41.2" r=".51"/>
<circle cx="202.6" cy="125" r=".51"/>
<circle cx="268.7" cy="125" r=".51"/>
<circle cx="228" cy="216.4" r=".51"/>
<circle cx="197.6" cy="140.3" r=".51"/>
<circle cx="57.9" cy="43.8" r=".51"/>
</g>
<use href="#words"/>
</svg>
